VERSION 5.7 ;
  NOWIREEXTENSIONATPIN ON ;
  DIVIDERCHAR "/" ;
  BUSBITCHARS "[]" ;
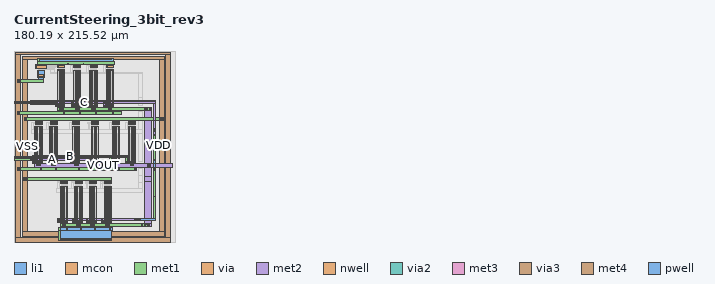
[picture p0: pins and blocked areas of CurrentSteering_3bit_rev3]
MACRO CurrentSteering_3bit_rev3
  CLASS BLOCK ;
  FOREIGN CurrentSteering_3bit_rev3 ;
  ORIGIN -36.730 137.180 ;
  SIZE 180.190 BY 215.520 ;
  PIN A
    ANTENNAGATEAREA 400.000000 ;
    PORT
      LAYER li1 ;
        RECT 103.560 -6.460 104.060 -6.290 ;
        RECT 104.350 -6.460 104.850 -6.290 ;
        RECT 105.140 -6.460 105.640 -6.290 ;
        RECT 105.930 -6.460 106.430 -6.290 ;
        RECT 106.720 -6.460 107.220 -6.290 ;
        RECT 107.510 -6.460 108.010 -6.290 ;
        RECT 108.300 -6.460 108.800 -6.290 ;
        RECT 109.090 -6.460 109.590 -6.290 ;
        RECT 109.880 -6.460 110.380 -6.290 ;
        RECT 110.670 -6.460 111.170 -6.290 ;
        RECT 124.580 -6.460 125.080 -6.290 ;
        RECT 125.370 -6.460 125.870 -6.290 ;
        RECT 126.160 -6.460 126.660 -6.290 ;
        RECT 126.950 -6.460 127.450 -6.290 ;
        RECT 127.740 -6.460 128.240 -6.290 ;
        RECT 128.530 -6.460 129.030 -6.290 ;
        RECT 129.320 -6.460 129.820 -6.290 ;
        RECT 130.110 -6.460 130.610 -6.290 ;
        RECT 130.900 -6.460 131.400 -6.290 ;
        RECT 131.690 -6.460 132.190 -6.290 ;
        RECT 103.560 -47.010 104.060 -46.840 ;
        RECT 104.350 -47.010 104.850 -46.840 ;
        RECT 105.140 -47.010 105.640 -46.840 ;
        RECT 105.930 -47.010 106.430 -46.840 ;
        RECT 106.720 -47.010 107.220 -46.840 ;
        RECT 107.510 -47.010 108.010 -46.840 ;
        RECT 108.300 -47.010 108.800 -46.840 ;
        RECT 109.090 -47.010 109.590 -46.840 ;
        RECT 109.880 -47.010 110.380 -46.840 ;
        RECT 110.670 -47.010 111.170 -46.840 ;
        RECT 124.580 -47.010 125.080 -46.840 ;
        RECT 125.370 -47.010 125.870 -46.840 ;
        RECT 126.160 -47.010 126.660 -46.840 ;
        RECT 126.950 -47.010 127.450 -46.840 ;
        RECT 127.740 -47.010 128.240 -46.840 ;
        RECT 128.530 -47.010 129.030 -46.840 ;
        RECT 129.320 -47.010 129.820 -46.840 ;
        RECT 130.110 -47.010 130.610 -46.840 ;
        RECT 130.900 -47.010 131.400 -46.840 ;
        RECT 131.690 -47.010 132.190 -46.840 ;
      LAYER mcon ;
        RECT 103.640 -6.460 103.980 -6.290 ;
        RECT 104.430 -6.460 104.770 -6.290 ;
        RECT 105.220 -6.460 105.560 -6.290 ;
        RECT 106.010 -6.460 106.350 -6.290 ;
        RECT 106.800 -6.460 107.140 -6.290 ;
        RECT 107.590 -6.460 107.930 -6.290 ;
        RECT 108.380 -6.460 108.720 -6.290 ;
        RECT 109.170 -6.460 109.510 -6.290 ;
        RECT 109.960 -6.460 110.300 -6.290 ;
        RECT 110.750 -6.460 111.090 -6.290 ;
        RECT 124.660 -6.460 125.000 -6.290 ;
        RECT 125.450 -6.460 125.790 -6.290 ;
        RECT 126.240 -6.460 126.580 -6.290 ;
        RECT 127.030 -6.460 127.370 -6.290 ;
        RECT 127.820 -6.460 128.160 -6.290 ;
        RECT 128.610 -6.460 128.950 -6.290 ;
        RECT 129.400 -6.460 129.740 -6.290 ;
        RECT 130.190 -6.460 130.530 -6.290 ;
        RECT 130.980 -6.460 131.320 -6.290 ;
        RECT 131.770 -6.460 132.110 -6.290 ;
        RECT 103.640 -47.010 103.980 -46.840 ;
        RECT 104.430 -47.010 104.770 -46.840 ;
        RECT 105.220 -47.010 105.560 -46.840 ;
        RECT 106.010 -47.010 106.350 -46.840 ;
        RECT 106.800 -47.010 107.140 -46.840 ;
        RECT 107.590 -47.010 107.930 -46.840 ;
        RECT 108.380 -47.010 108.720 -46.840 ;
        RECT 109.170 -47.010 109.510 -46.840 ;
        RECT 109.960 -47.010 110.300 -46.840 ;
        RECT 110.750 -47.010 111.090 -46.840 ;
        RECT 124.660 -47.010 125.000 -46.840 ;
        RECT 125.450 -47.010 125.790 -46.840 ;
        RECT 126.240 -47.010 126.580 -46.840 ;
        RECT 127.030 -47.010 127.370 -46.840 ;
        RECT 127.820 -47.010 128.160 -46.840 ;
        RECT 128.610 -47.010 128.950 -46.840 ;
        RECT 129.400 -47.010 129.740 -46.840 ;
        RECT 130.190 -47.010 130.530 -46.840 ;
        RECT 130.980 -47.010 131.320 -46.840 ;
        RECT 131.770 -47.010 132.110 -46.840 ;
      LAYER met1 ;
        RECT 103.580 -6.490 104.040 -6.260 ;
        RECT 104.370 -6.490 104.830 -6.260 ;
        RECT 105.160 -6.490 105.620 -6.260 ;
        RECT 105.950 -6.490 106.410 -6.260 ;
        RECT 106.740 -6.490 107.200 -6.260 ;
        RECT 107.530 -6.490 107.990 -6.260 ;
        RECT 108.320 -6.490 108.780 -6.260 ;
        RECT 109.110 -6.490 109.570 -6.260 ;
        RECT 109.900 -6.490 110.360 -6.260 ;
        RECT 110.690 -6.490 111.150 -6.260 ;
        RECT 124.600 -6.490 125.060 -6.260 ;
        RECT 125.390 -6.490 125.850 -6.260 ;
        RECT 126.180 -6.490 126.640 -6.260 ;
        RECT 126.970 -6.490 127.430 -6.260 ;
        RECT 127.760 -6.490 128.220 -6.260 ;
        RECT 128.550 -6.490 129.010 -6.260 ;
        RECT 129.340 -6.490 129.800 -6.260 ;
        RECT 130.130 -6.490 130.590 -6.260 ;
        RECT 130.920 -6.490 131.380 -6.260 ;
        RECT 131.710 -6.490 132.170 -6.260 ;
        RECT 36.820 -44.710 56.630 -42.990 ;
        RECT 100.420 -46.630 102.110 -43.730 ;
        RECT 121.430 -46.630 123.170 -43.610 ;
        RECT 100.420 -46.810 102.230 -46.630 ;
        RECT 121.430 -46.810 123.250 -46.630 ;
        RECT 100.420 -47.230 111.190 -46.810 ;
        RECT 121.430 -47.230 132.210 -46.810 ;
        RECT 100.420 -47.500 102.230 -47.230 ;
        RECT 121.430 -47.500 123.250 -47.230 ;
        RECT 100.420 -47.790 102.110 -47.500 ;
        RECT 121.430 -47.800 123.170 -47.500 ;
      LAYER via ;
        RECT 55.340 -44.390 56.190 -43.540 ;
        RECT 100.800 -44.530 101.880 -43.850 ;
        RECT 121.860 -44.510 122.590 -44.040 ;
        RECT 100.650 -47.550 101.730 -46.870 ;
        RECT 121.960 -47.540 122.690 -47.070 ;
      LAYER met2 ;
        RECT 57.260 -42.990 123.170 -42.980 ;
        RECT 36.820 -44.680 123.170 -42.990 ;
        RECT 36.820 -44.710 56.630 -44.680 ;
        RECT 57.260 -44.690 123.170 -44.680 ;
        RECT 100.420 -47.790 102.110 -44.690 ;
        RECT 121.430 -47.800 123.170 -44.690 ;
    END
  END A
  PIN B
    ANTENNAGATEAREA 800.000000 ;
    PORT
      LAYER li1 ;
        RECT 60.670 -6.440 61.170 -6.270 ;
        RECT 61.460 -6.440 61.960 -6.270 ;
        RECT 62.250 -6.440 62.750 -6.270 ;
        RECT 63.040 -6.440 63.540 -6.270 ;
        RECT 63.830 -6.440 64.330 -6.270 ;
        RECT 64.620 -6.440 65.120 -6.270 ;
        RECT 65.410 -6.440 65.910 -6.270 ;
        RECT 66.200 -6.440 66.700 -6.270 ;
        RECT 66.990 -6.440 67.490 -6.270 ;
        RECT 67.780 -6.440 68.280 -6.270 ;
        RECT 77.720 -6.440 78.220 -6.270 ;
        RECT 78.510 -6.440 79.010 -6.270 ;
        RECT 79.300 -6.440 79.800 -6.270 ;
        RECT 80.090 -6.440 80.590 -6.270 ;
        RECT 80.880 -6.440 81.380 -6.270 ;
        RECT 81.670 -6.440 82.170 -6.270 ;
        RECT 82.460 -6.440 82.960 -6.270 ;
        RECT 83.250 -6.440 83.750 -6.270 ;
        RECT 84.040 -6.440 84.540 -6.270 ;
        RECT 84.830 -6.440 85.330 -6.270 ;
        RECT 148.650 -6.490 149.150 -6.320 ;
        RECT 149.440 -6.490 149.940 -6.320 ;
        RECT 150.230 -6.490 150.730 -6.320 ;
        RECT 151.020 -6.490 151.520 -6.320 ;
        RECT 151.810 -6.490 152.310 -6.320 ;
        RECT 152.600 -6.490 153.100 -6.320 ;
        RECT 153.390 -6.490 153.890 -6.320 ;
        RECT 154.180 -6.490 154.680 -6.320 ;
        RECT 154.970 -6.490 155.470 -6.320 ;
        RECT 155.760 -6.490 156.260 -6.320 ;
        RECT 166.720 -6.490 167.220 -6.320 ;
        RECT 167.510 -6.490 168.010 -6.320 ;
        RECT 168.300 -6.490 168.800 -6.320 ;
        RECT 169.090 -6.490 169.590 -6.320 ;
        RECT 169.880 -6.490 170.380 -6.320 ;
        RECT 170.670 -6.490 171.170 -6.320 ;
        RECT 171.460 -6.490 171.960 -6.320 ;
        RECT 172.250 -6.490 172.750 -6.320 ;
        RECT 173.040 -6.490 173.540 -6.320 ;
        RECT 173.830 -6.490 174.330 -6.320 ;
        RECT 60.670 -46.990 61.170 -46.820 ;
        RECT 61.460 -46.990 61.960 -46.820 ;
        RECT 62.250 -46.990 62.750 -46.820 ;
        RECT 63.040 -46.990 63.540 -46.820 ;
        RECT 63.830 -46.990 64.330 -46.820 ;
        RECT 64.620 -46.990 65.120 -46.820 ;
        RECT 65.410 -46.990 65.910 -46.820 ;
        RECT 66.200 -46.990 66.700 -46.820 ;
        RECT 66.990 -46.990 67.490 -46.820 ;
        RECT 67.780 -46.990 68.280 -46.820 ;
        RECT 77.720 -46.990 78.220 -46.820 ;
        RECT 78.510 -46.990 79.010 -46.820 ;
        RECT 79.300 -46.990 79.800 -46.820 ;
        RECT 80.090 -46.990 80.590 -46.820 ;
        RECT 80.880 -46.990 81.380 -46.820 ;
        RECT 81.670 -46.990 82.170 -46.820 ;
        RECT 82.460 -46.990 82.960 -46.820 ;
        RECT 83.250 -46.990 83.750 -46.820 ;
        RECT 84.040 -46.990 84.540 -46.820 ;
        RECT 84.830 -46.990 85.330 -46.820 ;
        RECT 148.650 -47.040 149.150 -46.870 ;
        RECT 149.440 -47.040 149.940 -46.870 ;
        RECT 150.230 -47.040 150.730 -46.870 ;
        RECT 151.020 -47.040 151.520 -46.870 ;
        RECT 151.810 -47.040 152.310 -46.870 ;
        RECT 152.600 -47.040 153.100 -46.870 ;
        RECT 153.390 -47.040 153.890 -46.870 ;
        RECT 154.180 -47.040 154.680 -46.870 ;
        RECT 154.970 -47.040 155.470 -46.870 ;
        RECT 155.760 -47.040 156.260 -46.870 ;
        RECT 166.720 -47.040 167.220 -46.870 ;
        RECT 167.510 -47.040 168.010 -46.870 ;
        RECT 168.300 -47.040 168.800 -46.870 ;
        RECT 169.090 -47.040 169.590 -46.870 ;
        RECT 169.880 -47.040 170.380 -46.870 ;
        RECT 170.670 -47.040 171.170 -46.870 ;
        RECT 171.460 -47.040 171.960 -46.870 ;
        RECT 172.250 -47.040 172.750 -46.870 ;
        RECT 173.040 -47.040 173.540 -46.870 ;
        RECT 173.830 -47.040 174.330 -46.870 ;
      LAYER mcon ;
        RECT 60.750 -6.440 61.090 -6.270 ;
        RECT 61.540 -6.440 61.880 -6.270 ;
        RECT 62.330 -6.440 62.670 -6.270 ;
        RECT 63.120 -6.440 63.460 -6.270 ;
        RECT 63.910 -6.440 64.250 -6.270 ;
        RECT 64.700 -6.440 65.040 -6.270 ;
        RECT 65.490 -6.440 65.830 -6.270 ;
        RECT 66.280 -6.440 66.620 -6.270 ;
        RECT 67.070 -6.440 67.410 -6.270 ;
        RECT 67.860 -6.440 68.200 -6.270 ;
        RECT 77.800 -6.440 78.140 -6.270 ;
        RECT 78.590 -6.440 78.930 -6.270 ;
        RECT 79.380 -6.440 79.720 -6.270 ;
        RECT 80.170 -6.440 80.510 -6.270 ;
        RECT 80.960 -6.440 81.300 -6.270 ;
        RECT 81.750 -6.440 82.090 -6.270 ;
        RECT 82.540 -6.440 82.880 -6.270 ;
        RECT 83.330 -6.440 83.670 -6.270 ;
        RECT 84.120 -6.440 84.460 -6.270 ;
        RECT 84.910 -6.440 85.250 -6.270 ;
        RECT 148.730 -6.490 149.070 -6.320 ;
        RECT 149.520 -6.490 149.860 -6.320 ;
        RECT 150.310 -6.490 150.650 -6.320 ;
        RECT 151.100 -6.490 151.440 -6.320 ;
        RECT 151.890 -6.490 152.230 -6.320 ;
        RECT 152.680 -6.490 153.020 -6.320 ;
        RECT 153.470 -6.490 153.810 -6.320 ;
        RECT 154.260 -6.490 154.600 -6.320 ;
        RECT 155.050 -6.490 155.390 -6.320 ;
        RECT 155.840 -6.490 156.180 -6.320 ;
        RECT 166.800 -6.490 167.140 -6.320 ;
        RECT 167.590 -6.490 167.930 -6.320 ;
        RECT 168.380 -6.490 168.720 -6.320 ;
        RECT 169.170 -6.490 169.510 -6.320 ;
        RECT 169.960 -6.490 170.300 -6.320 ;
        RECT 170.750 -6.490 171.090 -6.320 ;
        RECT 171.540 -6.490 171.880 -6.320 ;
        RECT 172.330 -6.490 172.670 -6.320 ;
        RECT 173.120 -6.490 173.460 -6.320 ;
        RECT 173.910 -6.490 174.250 -6.320 ;
        RECT 60.750 -46.990 61.090 -46.820 ;
        RECT 61.540 -46.990 61.880 -46.820 ;
        RECT 62.330 -46.990 62.670 -46.820 ;
        RECT 63.120 -46.990 63.460 -46.820 ;
        RECT 63.910 -46.990 64.250 -46.820 ;
        RECT 64.700 -46.990 65.040 -46.820 ;
        RECT 65.490 -46.990 65.830 -46.820 ;
        RECT 66.280 -46.990 66.620 -46.820 ;
        RECT 67.070 -46.990 67.410 -46.820 ;
        RECT 67.860 -46.990 68.200 -46.820 ;
        RECT 77.800 -46.990 78.140 -46.820 ;
        RECT 78.590 -46.990 78.930 -46.820 ;
        RECT 79.380 -46.990 79.720 -46.820 ;
        RECT 80.170 -46.990 80.510 -46.820 ;
        RECT 80.960 -46.990 81.300 -46.820 ;
        RECT 81.750 -46.990 82.090 -46.820 ;
        RECT 82.540 -46.990 82.880 -46.820 ;
        RECT 83.330 -46.990 83.670 -46.820 ;
        RECT 84.120 -46.990 84.460 -46.820 ;
        RECT 84.910 -46.990 85.250 -46.820 ;
        RECT 148.730 -47.040 149.070 -46.870 ;
        RECT 149.520 -47.040 149.860 -46.870 ;
        RECT 150.310 -47.040 150.650 -46.870 ;
        RECT 151.100 -47.040 151.440 -46.870 ;
        RECT 151.890 -47.040 152.230 -46.870 ;
        RECT 152.680 -47.040 153.020 -46.870 ;
        RECT 153.470 -47.040 153.810 -46.870 ;
        RECT 154.260 -47.040 154.600 -46.870 ;
        RECT 155.050 -47.040 155.390 -46.870 ;
        RECT 155.840 -47.040 156.180 -46.870 ;
        RECT 166.800 -47.040 167.140 -46.870 ;
        RECT 167.590 -47.040 167.930 -46.870 ;
        RECT 168.380 -47.040 168.720 -46.870 ;
        RECT 169.170 -47.040 169.510 -46.870 ;
        RECT 169.960 -47.040 170.300 -46.870 ;
        RECT 170.750 -47.040 171.090 -46.870 ;
        RECT 171.540 -47.040 171.880 -46.870 ;
        RECT 172.330 -47.040 172.670 -46.870 ;
        RECT 173.120 -47.040 173.460 -46.870 ;
        RECT 173.910 -47.040 174.250 -46.870 ;
      LAYER met1 ;
        RECT 60.690 -6.470 61.150 -6.240 ;
        RECT 61.480 -6.470 61.940 -6.240 ;
        RECT 62.270 -6.470 62.730 -6.240 ;
        RECT 63.060 -6.470 63.520 -6.240 ;
        RECT 63.850 -6.470 64.310 -6.240 ;
        RECT 64.640 -6.470 65.100 -6.240 ;
        RECT 65.430 -6.470 65.890 -6.240 ;
        RECT 66.220 -6.470 66.680 -6.240 ;
        RECT 67.010 -6.470 67.470 -6.240 ;
        RECT 67.800 -6.470 68.260 -6.240 ;
        RECT 77.740 -6.470 78.200 -6.240 ;
        RECT 78.530 -6.470 78.990 -6.240 ;
        RECT 79.320 -6.470 79.780 -6.240 ;
        RECT 80.110 -6.470 80.570 -6.240 ;
        RECT 80.900 -6.470 81.360 -6.240 ;
        RECT 81.690 -6.470 82.150 -6.240 ;
        RECT 82.480 -6.470 82.940 -6.240 ;
        RECT 83.270 -6.470 83.730 -6.240 ;
        RECT 84.060 -6.470 84.520 -6.240 ;
        RECT 84.850 -6.470 85.310 -6.240 ;
        RECT 148.670 -6.520 149.130 -6.290 ;
        RECT 149.460 -6.520 149.920 -6.290 ;
        RECT 150.250 -6.520 150.710 -6.290 ;
        RECT 151.040 -6.520 151.500 -6.290 ;
        RECT 151.830 -6.520 152.290 -6.290 ;
        RECT 152.620 -6.520 153.080 -6.290 ;
        RECT 153.410 -6.520 153.870 -6.290 ;
        RECT 154.200 -6.520 154.660 -6.290 ;
        RECT 154.990 -6.520 155.450 -6.290 ;
        RECT 155.780 -6.520 156.240 -6.290 ;
        RECT 166.740 -6.520 167.200 -6.290 ;
        RECT 167.530 -6.520 167.990 -6.290 ;
        RECT 168.320 -6.520 168.780 -6.290 ;
        RECT 169.110 -6.520 169.570 -6.290 ;
        RECT 169.900 -6.520 170.360 -6.290 ;
        RECT 170.690 -6.520 171.150 -6.290 ;
        RECT 171.480 -6.520 171.940 -6.290 ;
        RECT 172.270 -6.520 172.730 -6.290 ;
        RECT 173.060 -6.520 173.520 -6.290 ;
        RECT 173.850 -6.520 174.310 -6.290 ;
        RECT 55.650 -39.750 58.240 -39.740 ;
        RECT 36.820 -40.080 58.240 -39.750 ;
        RECT 36.820 -41.430 59.140 -40.080 ;
        RECT 36.820 -41.540 57.000 -41.430 ;
        RECT 57.500 -46.250 59.140 -41.430 ;
        RECT 57.500 -46.610 59.150 -46.250 ;
        RECT 74.560 -46.610 76.200 -40.040 ;
        RECT 57.500 -46.790 59.340 -46.610 ;
        RECT 74.560 -46.790 76.390 -46.610 ;
        RECT 145.490 -46.660 147.220 -40.560 ;
        RECT 163.560 -46.300 165.050 -40.630 ;
        RECT 163.560 -46.660 165.200 -46.300 ;
        RECT 57.500 -47.210 68.300 -46.790 ;
        RECT 74.560 -47.210 85.350 -46.790 ;
        RECT 145.490 -46.840 147.320 -46.660 ;
        RECT 163.560 -46.840 165.390 -46.660 ;
        RECT 57.500 -47.480 59.340 -47.210 ;
        RECT 74.560 -47.480 76.390 -47.210 ;
        RECT 145.490 -47.260 156.280 -46.840 ;
        RECT 163.560 -47.260 174.350 -46.840 ;
        RECT 57.500 -47.770 59.150 -47.480 ;
        RECT 74.560 -47.770 76.200 -47.480 ;
        RECT 145.490 -47.530 147.320 -47.260 ;
        RECT 163.560 -47.530 165.390 -47.260 ;
        RECT 57.500 -47.810 59.140 -47.770 ;
        RECT 145.490 -47.850 147.220 -47.530 ;
        RECT 163.560 -47.820 165.200 -47.530 ;
        RECT 163.560 -47.870 165.050 -47.820 ;
      LAYER via ;
        RECT 55.250 -41.080 56.100 -40.230 ;
        RECT 57.780 -41.310 58.890 -40.150 ;
        RECT 74.810 -41.360 75.920 -40.200 ;
        RECT 145.890 -41.370 146.640 -40.830 ;
        RECT 163.750 -41.410 164.700 -40.900 ;
        RECT 146.020 -47.540 146.770 -47.000 ;
        RECT 163.830 -47.510 164.780 -47.000 ;
      LAYER met2 ;
        RECT 36.820 -39.780 57.000 -39.750 ;
        RECT 57.300 -39.780 165.060 -39.620 ;
        RECT 36.820 -41.470 165.060 -39.780 ;
        RECT 36.820 -41.540 57.000 -41.470 ;
        RECT 57.300 -41.540 165.060 -41.470 ;
        RECT 145.490 -47.850 147.220 -41.540 ;
        RECT 163.560 -47.870 165.050 -41.540 ;
    END
  END B
  PIN C
    ANTENNAGATEAREA 1600.000000 ;
    PORT
      LAYER li1 ;
        RECT 86.480 57.790 86.980 57.960 ;
        RECT 87.270 57.790 87.770 57.960 ;
        RECT 88.060 57.790 88.560 57.960 ;
        RECT 88.850 57.790 89.350 57.960 ;
        RECT 89.640 57.790 90.140 57.960 ;
        RECT 90.430 57.790 90.930 57.960 ;
        RECT 91.220 57.790 91.720 57.960 ;
        RECT 92.010 57.790 92.510 57.960 ;
        RECT 92.800 57.790 93.300 57.960 ;
        RECT 93.590 57.790 94.090 57.960 ;
        RECT 104.710 57.630 105.210 57.800 ;
        RECT 105.500 57.630 106.000 57.800 ;
        RECT 106.290 57.630 106.790 57.800 ;
        RECT 107.080 57.630 107.580 57.800 ;
        RECT 107.870 57.630 108.370 57.800 ;
        RECT 108.660 57.630 109.160 57.800 ;
        RECT 109.450 57.630 109.950 57.800 ;
        RECT 110.240 57.630 110.740 57.800 ;
        RECT 111.030 57.630 111.530 57.800 ;
        RECT 111.820 57.630 112.320 57.800 ;
        RECT 123.110 57.580 123.610 57.750 ;
        RECT 123.900 57.580 124.400 57.750 ;
        RECT 124.690 57.580 125.190 57.750 ;
        RECT 125.480 57.580 125.980 57.750 ;
        RECT 126.270 57.580 126.770 57.750 ;
        RECT 127.060 57.580 127.560 57.750 ;
        RECT 127.850 57.580 128.350 57.750 ;
        RECT 128.640 57.580 129.140 57.750 ;
        RECT 129.430 57.580 129.930 57.750 ;
        RECT 130.220 57.580 130.720 57.750 ;
        RECT 141.880 57.730 142.380 57.900 ;
        RECT 142.670 57.730 143.170 57.900 ;
        RECT 143.460 57.730 143.960 57.900 ;
        RECT 144.250 57.730 144.750 57.900 ;
        RECT 145.040 57.730 145.540 57.900 ;
        RECT 145.830 57.730 146.330 57.900 ;
        RECT 146.620 57.730 147.120 57.900 ;
        RECT 147.410 57.730 147.910 57.900 ;
        RECT 148.200 57.730 148.700 57.900 ;
        RECT 148.990 57.730 149.490 57.900 ;
        RECT 86.480 17.240 86.980 17.410 ;
        RECT 87.270 17.240 87.770 17.410 ;
        RECT 88.060 17.240 88.560 17.410 ;
        RECT 88.850 17.240 89.350 17.410 ;
        RECT 89.640 17.240 90.140 17.410 ;
        RECT 90.430 17.240 90.930 17.410 ;
        RECT 91.220 17.240 91.720 17.410 ;
        RECT 92.010 17.240 92.510 17.410 ;
        RECT 92.800 17.240 93.300 17.410 ;
        RECT 93.590 17.240 94.090 17.410 ;
        RECT 104.710 17.080 105.210 17.250 ;
        RECT 105.500 17.080 106.000 17.250 ;
        RECT 106.290 17.080 106.790 17.250 ;
        RECT 107.080 17.080 107.580 17.250 ;
        RECT 107.870 17.080 108.370 17.250 ;
        RECT 108.660 17.080 109.160 17.250 ;
        RECT 109.450 17.080 109.950 17.250 ;
        RECT 110.240 17.080 110.740 17.250 ;
        RECT 111.030 17.080 111.530 17.250 ;
        RECT 111.820 17.080 112.320 17.250 ;
        RECT 123.110 17.030 123.610 17.200 ;
        RECT 123.900 17.030 124.400 17.200 ;
        RECT 124.690 17.030 125.190 17.200 ;
        RECT 125.480 17.030 125.980 17.200 ;
        RECT 126.270 17.030 126.770 17.200 ;
        RECT 127.060 17.030 127.560 17.200 ;
        RECT 127.850 17.030 128.350 17.200 ;
        RECT 128.640 17.030 129.140 17.200 ;
        RECT 129.430 17.030 129.930 17.200 ;
        RECT 130.220 17.030 130.720 17.200 ;
        RECT 141.880 17.180 142.380 17.350 ;
        RECT 142.670 17.180 143.170 17.350 ;
        RECT 143.460 17.180 143.960 17.350 ;
        RECT 144.250 17.180 144.750 17.350 ;
        RECT 145.040 17.180 145.540 17.350 ;
        RECT 145.830 17.180 146.330 17.350 ;
        RECT 146.620 17.180 147.120 17.350 ;
        RECT 147.410 17.180 147.910 17.350 ;
        RECT 148.200 17.180 148.700 17.350 ;
        RECT 148.990 17.180 149.490 17.350 ;
        RECT 89.760 -74.150 90.260 -73.980 ;
        RECT 90.550 -74.150 91.050 -73.980 ;
        RECT 91.340 -74.150 91.840 -73.980 ;
        RECT 92.130 -74.150 92.630 -73.980 ;
        RECT 92.920 -74.150 93.420 -73.980 ;
        RECT 93.710 -74.150 94.210 -73.980 ;
        RECT 94.500 -74.150 95.000 -73.980 ;
        RECT 95.290 -74.150 95.790 -73.980 ;
        RECT 96.080 -74.150 96.580 -73.980 ;
        RECT 96.870 -74.150 97.370 -73.980 ;
        RECT 106.150 -74.150 106.650 -73.980 ;
        RECT 106.940 -74.150 107.440 -73.980 ;
        RECT 107.730 -74.150 108.230 -73.980 ;
        RECT 108.520 -74.150 109.020 -73.980 ;
        RECT 109.310 -74.150 109.810 -73.980 ;
        RECT 110.100 -74.150 110.600 -73.980 ;
        RECT 110.890 -74.150 111.390 -73.980 ;
        RECT 111.680 -74.150 112.180 -73.980 ;
        RECT 112.470 -74.150 112.970 -73.980 ;
        RECT 113.260 -74.150 113.760 -73.980 ;
        RECT 122.110 -74.150 122.610 -73.980 ;
        RECT 122.900 -74.150 123.400 -73.980 ;
        RECT 123.690 -74.150 124.190 -73.980 ;
        RECT 124.480 -74.150 124.980 -73.980 ;
        RECT 125.270 -74.150 125.770 -73.980 ;
        RECT 126.060 -74.150 126.560 -73.980 ;
        RECT 126.850 -74.150 127.350 -73.980 ;
        RECT 127.640 -74.150 128.140 -73.980 ;
        RECT 128.430 -74.150 128.930 -73.980 ;
        RECT 129.220 -74.150 129.720 -73.980 ;
        RECT 139.100 -74.150 139.600 -73.980 ;
        RECT 139.890 -74.150 140.390 -73.980 ;
        RECT 140.680 -74.150 141.180 -73.980 ;
        RECT 141.470 -74.150 141.970 -73.980 ;
        RECT 142.260 -74.150 142.760 -73.980 ;
        RECT 143.050 -74.150 143.550 -73.980 ;
        RECT 143.840 -74.150 144.340 -73.980 ;
        RECT 144.630 -74.150 145.130 -73.980 ;
        RECT 145.420 -74.150 145.920 -73.980 ;
        RECT 146.210 -74.150 146.710 -73.980 ;
        RECT 194.450 -110.000 197.690 -8.410 ;
        RECT 173.110 -112.650 197.690 -110.000 ;
        RECT 173.110 -112.710 197.640 -112.650 ;
        RECT 194.450 -112.750 197.640 -112.710 ;
        RECT 89.760 -114.700 90.260 -114.530 ;
        RECT 90.550 -114.700 91.050 -114.530 ;
        RECT 91.340 -114.700 91.840 -114.530 ;
        RECT 92.130 -114.700 92.630 -114.530 ;
        RECT 92.920 -114.700 93.420 -114.530 ;
        RECT 93.710 -114.700 94.210 -114.530 ;
        RECT 94.500 -114.700 95.000 -114.530 ;
        RECT 95.290 -114.700 95.790 -114.530 ;
        RECT 96.080 -114.700 96.580 -114.530 ;
        RECT 96.870 -114.700 97.370 -114.530 ;
        RECT 106.150 -114.700 106.650 -114.530 ;
        RECT 106.940 -114.700 107.440 -114.530 ;
        RECT 107.730 -114.700 108.230 -114.530 ;
        RECT 108.520 -114.700 109.020 -114.530 ;
        RECT 109.310 -114.700 109.810 -114.530 ;
        RECT 110.100 -114.700 110.600 -114.530 ;
        RECT 110.890 -114.700 111.390 -114.530 ;
        RECT 111.680 -114.700 112.180 -114.530 ;
        RECT 112.470 -114.700 112.970 -114.530 ;
        RECT 113.260 -114.700 113.760 -114.530 ;
        RECT 122.110 -114.700 122.610 -114.530 ;
        RECT 122.900 -114.700 123.400 -114.530 ;
        RECT 123.690 -114.700 124.190 -114.530 ;
        RECT 124.480 -114.700 124.980 -114.530 ;
        RECT 125.270 -114.700 125.770 -114.530 ;
        RECT 126.060 -114.700 126.560 -114.530 ;
        RECT 126.850 -114.700 127.350 -114.530 ;
        RECT 127.640 -114.700 128.140 -114.530 ;
        RECT 128.430 -114.700 128.930 -114.530 ;
        RECT 129.220 -114.700 129.720 -114.530 ;
        RECT 139.100 -114.700 139.600 -114.530 ;
        RECT 139.890 -114.700 140.390 -114.530 ;
        RECT 140.680 -114.700 141.180 -114.530 ;
        RECT 141.470 -114.700 141.970 -114.530 ;
        RECT 142.260 -114.700 142.760 -114.530 ;
        RECT 143.050 -114.700 143.550 -114.530 ;
        RECT 143.840 -114.700 144.340 -114.530 ;
        RECT 144.630 -114.700 145.130 -114.530 ;
        RECT 145.420 -114.700 145.920 -114.530 ;
        RECT 146.210 -114.700 146.710 -114.530 ;
      LAYER mcon ;
        RECT 86.560 57.790 86.900 57.960 ;
        RECT 87.350 57.790 87.690 57.960 ;
        RECT 88.140 57.790 88.480 57.960 ;
        RECT 88.930 57.790 89.270 57.960 ;
        RECT 89.720 57.790 90.060 57.960 ;
        RECT 90.510 57.790 90.850 57.960 ;
        RECT 91.300 57.790 91.640 57.960 ;
        RECT 92.090 57.790 92.430 57.960 ;
        RECT 92.880 57.790 93.220 57.960 ;
        RECT 93.670 57.790 94.010 57.960 ;
        RECT 104.790 57.630 105.130 57.800 ;
        RECT 105.580 57.630 105.920 57.800 ;
        RECT 106.370 57.630 106.710 57.800 ;
        RECT 107.160 57.630 107.500 57.800 ;
        RECT 107.950 57.630 108.290 57.800 ;
        RECT 108.740 57.630 109.080 57.800 ;
        RECT 109.530 57.630 109.870 57.800 ;
        RECT 110.320 57.630 110.660 57.800 ;
        RECT 111.110 57.630 111.450 57.800 ;
        RECT 111.900 57.630 112.240 57.800 ;
        RECT 123.190 57.580 123.530 57.750 ;
        RECT 123.980 57.580 124.320 57.750 ;
        RECT 124.770 57.580 125.110 57.750 ;
        RECT 125.560 57.580 125.900 57.750 ;
        RECT 126.350 57.580 126.690 57.750 ;
        RECT 127.140 57.580 127.480 57.750 ;
        RECT 127.930 57.580 128.270 57.750 ;
        RECT 128.720 57.580 129.060 57.750 ;
        RECT 129.510 57.580 129.850 57.750 ;
        RECT 130.300 57.580 130.640 57.750 ;
        RECT 141.960 57.730 142.300 57.900 ;
        RECT 142.750 57.730 143.090 57.900 ;
        RECT 143.540 57.730 143.880 57.900 ;
        RECT 144.330 57.730 144.670 57.900 ;
        RECT 145.120 57.730 145.460 57.900 ;
        RECT 145.910 57.730 146.250 57.900 ;
        RECT 146.700 57.730 147.040 57.900 ;
        RECT 147.490 57.730 147.830 57.900 ;
        RECT 148.280 57.730 148.620 57.900 ;
        RECT 149.070 57.730 149.410 57.900 ;
        RECT 86.560 17.240 86.900 17.410 ;
        RECT 87.350 17.240 87.690 17.410 ;
        RECT 88.140 17.240 88.480 17.410 ;
        RECT 88.930 17.240 89.270 17.410 ;
        RECT 89.720 17.240 90.060 17.410 ;
        RECT 90.510 17.240 90.850 17.410 ;
        RECT 91.300 17.240 91.640 17.410 ;
        RECT 92.090 17.240 92.430 17.410 ;
        RECT 92.880 17.240 93.220 17.410 ;
        RECT 93.670 17.240 94.010 17.410 ;
        RECT 104.790 17.080 105.130 17.250 ;
        RECT 105.580 17.080 105.920 17.250 ;
        RECT 106.370 17.080 106.710 17.250 ;
        RECT 107.160 17.080 107.500 17.250 ;
        RECT 107.950 17.080 108.290 17.250 ;
        RECT 108.740 17.080 109.080 17.250 ;
        RECT 109.530 17.080 109.870 17.250 ;
        RECT 110.320 17.080 110.660 17.250 ;
        RECT 111.110 17.080 111.450 17.250 ;
        RECT 111.900 17.080 112.240 17.250 ;
        RECT 123.190 17.030 123.530 17.200 ;
        RECT 123.980 17.030 124.320 17.200 ;
        RECT 124.770 17.030 125.110 17.200 ;
        RECT 125.560 17.030 125.900 17.200 ;
        RECT 126.350 17.030 126.690 17.200 ;
        RECT 127.140 17.030 127.480 17.200 ;
        RECT 127.930 17.030 128.270 17.200 ;
        RECT 128.720 17.030 129.060 17.200 ;
        RECT 129.510 17.030 129.850 17.200 ;
        RECT 130.300 17.030 130.640 17.200 ;
        RECT 141.960 17.180 142.300 17.350 ;
        RECT 142.750 17.180 143.090 17.350 ;
        RECT 143.540 17.180 143.880 17.350 ;
        RECT 144.330 17.180 144.670 17.350 ;
        RECT 145.120 17.180 145.460 17.350 ;
        RECT 145.910 17.180 146.250 17.350 ;
        RECT 146.700 17.180 147.040 17.350 ;
        RECT 147.490 17.180 147.830 17.350 ;
        RECT 148.280 17.180 148.620 17.350 ;
        RECT 149.070 17.180 149.410 17.350 ;
        RECT 194.860 -10.520 195.580 -10.030 ;
        RECT 196.450 -10.570 197.170 -10.080 ;
        RECT 194.830 -11.610 195.550 -11.120 ;
        RECT 196.490 -11.620 197.210 -11.130 ;
        RECT 194.780 -15.480 195.500 -14.990 ;
        RECT 196.470 -15.510 197.190 -15.020 ;
        RECT 194.850 -16.810 195.570 -16.320 ;
        RECT 196.480 -16.850 197.200 -16.360 ;
        RECT 194.770 -43.680 195.490 -43.190 ;
        RECT 196.460 -43.620 197.180 -43.130 ;
        RECT 194.740 -44.520 195.460 -44.030 ;
        RECT 196.420 -44.520 197.140 -44.030 ;
        RECT 194.650 -54.660 195.370 -54.170 ;
        RECT 196.310 -54.650 197.030 -54.160 ;
        RECT 194.680 -55.840 195.400 -55.350 ;
        RECT 196.340 -55.810 197.060 -55.320 ;
        RECT 89.840 -74.150 90.180 -73.980 ;
        RECT 90.630 -74.150 90.970 -73.980 ;
        RECT 91.420 -74.150 91.760 -73.980 ;
        RECT 92.210 -74.150 92.550 -73.980 ;
        RECT 93.000 -74.150 93.340 -73.980 ;
        RECT 93.790 -74.150 94.130 -73.980 ;
        RECT 94.580 -74.150 94.920 -73.980 ;
        RECT 95.370 -74.150 95.710 -73.980 ;
        RECT 96.160 -74.150 96.500 -73.980 ;
        RECT 96.950 -74.150 97.290 -73.980 ;
        RECT 106.230 -74.150 106.570 -73.980 ;
        RECT 107.020 -74.150 107.360 -73.980 ;
        RECT 107.810 -74.150 108.150 -73.980 ;
        RECT 108.600 -74.150 108.940 -73.980 ;
        RECT 109.390 -74.150 109.730 -73.980 ;
        RECT 110.180 -74.150 110.520 -73.980 ;
        RECT 110.970 -74.150 111.310 -73.980 ;
        RECT 111.760 -74.150 112.100 -73.980 ;
        RECT 112.550 -74.150 112.890 -73.980 ;
        RECT 113.340 -74.150 113.680 -73.980 ;
        RECT 122.190 -74.150 122.530 -73.980 ;
        RECT 122.980 -74.150 123.320 -73.980 ;
        RECT 123.770 -74.150 124.110 -73.980 ;
        RECT 124.560 -74.150 124.900 -73.980 ;
        RECT 125.350 -74.150 125.690 -73.980 ;
        RECT 126.140 -74.150 126.480 -73.980 ;
        RECT 126.930 -74.150 127.270 -73.980 ;
        RECT 127.720 -74.150 128.060 -73.980 ;
        RECT 128.510 -74.150 128.850 -73.980 ;
        RECT 129.300 -74.150 129.640 -73.980 ;
        RECT 139.180 -74.150 139.520 -73.980 ;
        RECT 139.970 -74.150 140.310 -73.980 ;
        RECT 140.760 -74.150 141.100 -73.980 ;
        RECT 141.550 -74.150 141.890 -73.980 ;
        RECT 142.340 -74.150 142.680 -73.980 ;
        RECT 143.130 -74.150 143.470 -73.980 ;
        RECT 143.920 -74.150 144.260 -73.980 ;
        RECT 144.710 -74.150 145.050 -73.980 ;
        RECT 145.500 -74.150 145.840 -73.980 ;
        RECT 146.290 -74.150 146.630 -73.980 ;
        RECT 174.630 -110.960 175.410 -110.450 ;
        RECT 176.120 -111.010 176.840 -110.520 ;
        RECT 177.960 -111.070 178.680 -110.580 ;
        RECT 179.820 -111.090 180.540 -110.600 ;
        RECT 174.660 -112.460 175.440 -111.950 ;
        RECT 176.150 -112.440 176.930 -111.930 ;
        RECT 177.940 -112.430 178.660 -111.940 ;
        RECT 179.840 -112.490 180.560 -112.000 ;
        RECT 89.840 -114.700 90.180 -114.530 ;
        RECT 90.630 -114.700 90.970 -114.530 ;
        RECT 91.420 -114.700 91.760 -114.530 ;
        RECT 92.210 -114.700 92.550 -114.530 ;
        RECT 93.000 -114.700 93.340 -114.530 ;
        RECT 93.790 -114.700 94.130 -114.530 ;
        RECT 94.580 -114.700 94.920 -114.530 ;
        RECT 95.370 -114.700 95.710 -114.530 ;
        RECT 96.160 -114.700 96.500 -114.530 ;
        RECT 96.950 -114.700 97.290 -114.530 ;
        RECT 106.230 -114.700 106.570 -114.530 ;
        RECT 107.020 -114.700 107.360 -114.530 ;
        RECT 107.810 -114.700 108.150 -114.530 ;
        RECT 108.600 -114.700 108.940 -114.530 ;
        RECT 109.390 -114.700 109.730 -114.530 ;
        RECT 110.180 -114.700 110.520 -114.530 ;
        RECT 110.970 -114.700 111.310 -114.530 ;
        RECT 111.760 -114.700 112.100 -114.530 ;
        RECT 112.550 -114.700 112.890 -114.530 ;
        RECT 113.340 -114.700 113.680 -114.530 ;
        RECT 122.190 -114.700 122.530 -114.530 ;
        RECT 122.980 -114.700 123.320 -114.530 ;
        RECT 123.770 -114.700 124.110 -114.530 ;
        RECT 124.560 -114.700 124.900 -114.530 ;
        RECT 125.350 -114.700 125.690 -114.530 ;
        RECT 126.140 -114.700 126.480 -114.530 ;
        RECT 126.930 -114.700 127.270 -114.530 ;
        RECT 127.720 -114.700 128.060 -114.530 ;
        RECT 128.510 -114.700 128.850 -114.530 ;
        RECT 129.300 -114.700 129.640 -114.530 ;
        RECT 139.180 -114.700 139.520 -114.530 ;
        RECT 139.970 -114.700 140.310 -114.530 ;
        RECT 140.760 -114.700 141.100 -114.530 ;
        RECT 141.550 -114.700 141.890 -114.530 ;
        RECT 142.340 -114.700 142.680 -114.530 ;
        RECT 143.130 -114.700 143.470 -114.530 ;
        RECT 143.920 -114.700 144.260 -114.530 ;
        RECT 144.710 -114.700 145.050 -114.530 ;
        RECT 145.500 -114.700 145.840 -114.530 ;
        RECT 146.290 -114.700 146.630 -114.530 ;
      LAYER met1 ;
        RECT 86.500 57.760 86.960 57.990 ;
        RECT 87.290 57.760 87.750 57.990 ;
        RECT 88.080 57.760 88.540 57.990 ;
        RECT 88.870 57.760 89.330 57.990 ;
        RECT 89.660 57.760 90.120 57.990 ;
        RECT 90.450 57.760 90.910 57.990 ;
        RECT 91.240 57.760 91.700 57.990 ;
        RECT 92.030 57.760 92.490 57.990 ;
        RECT 92.820 57.760 93.280 57.990 ;
        RECT 93.610 57.760 94.070 57.990 ;
        RECT 104.730 57.600 105.190 57.830 ;
        RECT 105.520 57.600 105.980 57.830 ;
        RECT 106.310 57.600 106.770 57.830 ;
        RECT 107.100 57.600 107.560 57.830 ;
        RECT 107.890 57.600 108.350 57.830 ;
        RECT 108.680 57.600 109.140 57.830 ;
        RECT 109.470 57.600 109.930 57.830 ;
        RECT 110.260 57.600 110.720 57.830 ;
        RECT 111.050 57.600 111.510 57.830 ;
        RECT 111.840 57.600 112.300 57.830 ;
        RECT 123.130 57.550 123.590 57.780 ;
        RECT 123.920 57.550 124.380 57.780 ;
        RECT 124.710 57.550 125.170 57.780 ;
        RECT 125.500 57.550 125.960 57.780 ;
        RECT 126.290 57.550 126.750 57.780 ;
        RECT 127.080 57.550 127.540 57.780 ;
        RECT 127.870 57.550 128.330 57.780 ;
        RECT 128.660 57.550 129.120 57.780 ;
        RECT 129.450 57.550 129.910 57.780 ;
        RECT 130.240 57.550 130.700 57.780 ;
        RECT 141.900 57.700 142.360 57.930 ;
        RECT 142.690 57.700 143.150 57.930 ;
        RECT 143.480 57.700 143.940 57.930 ;
        RECT 144.270 57.700 144.730 57.930 ;
        RECT 145.060 57.700 145.520 57.930 ;
        RECT 145.850 57.700 146.310 57.930 ;
        RECT 146.640 57.700 147.100 57.930 ;
        RECT 147.430 57.700 147.890 57.930 ;
        RECT 148.220 57.700 148.680 57.930 ;
        RECT 149.010 57.700 149.470 57.930 ;
        RECT 55.650 22.090 84.860 22.840 ;
        RECT 36.730 21.210 84.860 22.090 ;
        RECT 36.730 19.660 84.990 21.210 ;
        RECT 55.650 19.070 84.990 19.660 ;
        RECT 83.330 17.620 84.990 19.070 ;
        RECT 83.330 17.440 85.150 17.620 ;
        RECT 101.570 17.460 103.230 21.050 ;
        RECT 83.330 17.020 94.110 17.440 ;
        RECT 101.570 17.280 103.380 17.460 ;
        RECT 119.970 17.410 121.630 20.990 ;
        RECT 138.730 17.560 140.390 21.120 ;
        RECT 83.330 16.750 85.150 17.020 ;
        RECT 101.570 16.860 112.340 17.280 ;
        RECT 119.970 17.230 121.780 17.410 ;
        RECT 138.730 17.380 140.550 17.560 ;
        RECT 83.330 16.460 84.990 16.750 ;
        RECT 101.570 16.590 103.380 16.860 ;
        RECT 119.970 16.810 130.740 17.230 ;
        RECT 138.730 16.960 149.510 17.380 ;
        RECT 101.570 16.300 103.230 16.590 ;
        RECT 119.970 16.540 121.780 16.810 ;
        RECT 138.730 16.690 140.550 16.960 ;
        RECT 119.970 16.240 121.630 16.540 ;
        RECT 138.730 16.370 140.390 16.690 ;
        RECT 194.450 -44.750 197.670 -8.300 ;
        RECT 89.780 -74.180 90.240 -73.950 ;
        RECT 90.570 -74.180 91.030 -73.950 ;
        RECT 91.360 -74.180 91.820 -73.950 ;
        RECT 92.150 -74.180 92.610 -73.950 ;
        RECT 92.940 -74.180 93.400 -73.950 ;
        RECT 93.730 -74.180 94.190 -73.950 ;
        RECT 94.520 -74.180 94.980 -73.950 ;
        RECT 95.310 -74.180 95.770 -73.950 ;
        RECT 96.100 -74.180 96.560 -73.950 ;
        RECT 96.890 -74.180 97.350 -73.950 ;
        RECT 106.170 -74.180 106.630 -73.950 ;
        RECT 106.960 -74.180 107.420 -73.950 ;
        RECT 107.750 -74.180 108.210 -73.950 ;
        RECT 108.540 -74.180 109.000 -73.950 ;
        RECT 109.330 -74.180 109.790 -73.950 ;
        RECT 110.120 -74.180 110.580 -73.950 ;
        RECT 110.910 -74.180 111.370 -73.950 ;
        RECT 111.700 -74.180 112.160 -73.950 ;
        RECT 112.490 -74.180 112.950 -73.950 ;
        RECT 113.280 -74.180 113.740 -73.950 ;
        RECT 122.130 -74.180 122.590 -73.950 ;
        RECT 122.920 -74.180 123.380 -73.950 ;
        RECT 123.710 -74.180 124.170 -73.950 ;
        RECT 124.500 -74.180 124.960 -73.950 ;
        RECT 125.290 -74.180 125.750 -73.950 ;
        RECT 126.080 -74.180 126.540 -73.950 ;
        RECT 126.870 -74.180 127.330 -73.950 ;
        RECT 127.660 -74.180 128.120 -73.950 ;
        RECT 128.450 -74.180 128.910 -73.950 ;
        RECT 129.240 -74.180 129.700 -73.950 ;
        RECT 139.120 -74.180 139.580 -73.950 ;
        RECT 139.910 -74.180 140.370 -73.950 ;
        RECT 140.700 -74.180 141.160 -73.950 ;
        RECT 141.490 -74.180 141.950 -73.950 ;
        RECT 142.280 -74.180 142.740 -73.950 ;
        RECT 143.070 -74.180 143.530 -73.950 ;
        RECT 143.860 -74.180 144.320 -73.950 ;
        RECT 144.650 -74.180 145.110 -73.950 ;
        RECT 145.440 -74.180 145.900 -73.950 ;
        RECT 146.230 -74.180 146.690 -73.950 ;
        RECT 194.450 -86.090 197.640 -53.700 ;
        RECT 194.450 -110.000 197.720 -86.090 ;
        RECT 86.520 -114.320 88.330 -110.690 ;
        RECT 103.000 -114.320 104.700 -111.150 ;
        RECT 118.950 -114.320 120.640 -111.440 ;
        RECT 135.930 -114.320 137.610 -112.190 ;
        RECT 173.110 -112.710 197.720 -110.000 ;
        RECT 194.450 -112.750 197.720 -112.710 ;
        RECT 86.520 -114.500 88.430 -114.320 ;
        RECT 103.000 -114.500 104.820 -114.320 ;
        RECT 118.950 -114.500 120.780 -114.320 ;
        RECT 135.930 -114.500 137.770 -114.320 ;
        RECT 86.520 -114.920 97.390 -114.500 ;
        RECT 103.000 -114.920 113.780 -114.500 ;
        RECT 118.950 -114.920 129.740 -114.500 ;
        RECT 135.930 -114.920 146.730 -114.500 ;
        RECT 86.520 -115.190 88.430 -114.920 ;
        RECT 103.000 -115.190 104.820 -114.920 ;
        RECT 118.950 -115.190 120.780 -114.920 ;
        RECT 135.930 -115.190 137.770 -114.920 ;
        RECT 86.520 -115.490 88.330 -115.190 ;
        RECT 103.000 -115.540 104.700 -115.190 ;
        RECT 118.950 -115.500 120.640 -115.190 ;
        RECT 135.930 -115.480 137.610 -115.190 ;
      LAYER via ;
        RECT 83.840 20.360 84.480 20.840 ;
        RECT 102.030 20.090 102.670 20.570 ;
        RECT 120.490 20.070 121.130 20.550 ;
        RECT 83.840 16.810 84.480 17.290 ;
        RECT 139.160 20.160 139.800 20.640 ;
        RECT 101.990 16.710 102.630 17.190 ;
        RECT 120.370 16.650 121.010 17.130 ;
        RECT 139.230 16.850 139.870 17.330 ;
        RECT 194.860 -9.330 195.580 -8.840 ;
        RECT 196.430 -9.300 197.150 -8.810 ;
        RECT 194.860 -10.520 195.580 -10.030 ;
        RECT 196.450 -10.570 197.170 -10.080 ;
        RECT 194.830 -11.610 195.550 -11.120 ;
        RECT 196.490 -11.620 197.210 -11.130 ;
        RECT 194.780 -15.480 195.500 -14.990 ;
        RECT 196.470 -15.510 197.190 -15.020 ;
        RECT 86.800 -112.240 87.980 -111.050 ;
        RECT 173.260 -110.980 174.040 -110.470 ;
        RECT 174.630 -110.960 175.410 -110.450 ;
        RECT 176.120 -111.010 176.840 -110.520 ;
        RECT 177.960 -111.070 178.680 -110.580 ;
        RECT 86.810 -115.270 87.990 -114.080 ;
        RECT 103.390 -112.290 104.400 -111.440 ;
        RECT 119.320 -112.470 120.220 -111.720 ;
        RECT 136.290 -112.940 137.240 -112.320 ;
        RECT 173.230 -112.610 174.010 -112.100 ;
        RECT 174.660 -112.460 175.440 -111.950 ;
        RECT 176.150 -112.440 176.930 -111.930 ;
        RECT 177.940 -112.430 178.660 -111.940 ;
        RECT 103.400 -115.210 104.410 -114.360 ;
        RECT 119.350 -115.280 120.250 -114.530 ;
        RECT 136.130 -115.290 137.080 -114.670 ;
      LAYER met2 ;
        RECT 161.060 22.890 191.140 22.900 ;
        RECT 161.060 22.870 197.700 22.890 ;
        RECT 83.210 22.840 197.700 22.870 ;
        RECT 55.650 22.810 197.700 22.840 ;
        RECT 55.650 22.090 197.730 22.810 ;
        RECT 36.730 19.740 197.730 22.090 ;
        RECT 36.730 19.660 84.990 19.740 ;
        RECT 55.650 19.070 84.990 19.660 ;
        RECT 83.330 16.460 84.990 19.070 ;
        RECT 101.570 16.300 103.230 19.740 ;
        RECT 119.970 16.240 121.630 19.740 ;
        RECT 138.730 16.370 140.390 19.740 ;
        RECT 161.060 19.720 197.730 19.740 ;
        RECT 188.640 19.700 197.730 19.720 ;
        RECT 194.560 -9.060 197.730 19.700 ;
        RECT 194.600 -15.810 197.730 -9.060 ;
        RECT 86.320 -112.770 179.530 -110.000 ;
        RECT 86.520 -115.490 88.330 -112.770 ;
        RECT 103.000 -115.540 104.700 -112.770 ;
        RECT 118.950 -115.500 120.640 -112.770 ;
        RECT 135.930 -115.480 137.610 -112.770 ;
    END
  END C
  PIN VOUT
    ANTENNADIFFAREA 974.399963 ;
    PORT
      LAYER li1 ;
        RECT 86.250 17.580 86.420 57.620 ;
        RECT 87.830 17.580 88.000 57.620 ;
        RECT 89.410 17.580 89.580 57.620 ;
        RECT 90.990 17.580 91.160 57.620 ;
        RECT 92.570 17.580 92.740 57.620 ;
        RECT 94.150 17.580 94.320 57.620 ;
        RECT 104.480 17.420 104.650 57.460 ;
        RECT 106.060 17.420 106.230 57.460 ;
        RECT 107.640 17.420 107.810 57.460 ;
        RECT 109.220 17.420 109.390 57.460 ;
        RECT 110.800 17.420 110.970 57.460 ;
        RECT 112.380 17.420 112.550 57.460 ;
        RECT 122.880 17.370 123.050 57.410 ;
        RECT 124.460 17.370 124.630 57.410 ;
        RECT 126.040 17.370 126.210 57.410 ;
        RECT 127.620 17.370 127.790 57.410 ;
        RECT 129.200 17.370 129.370 57.410 ;
        RECT 130.780 17.370 130.950 57.410 ;
        RECT 141.650 17.520 141.820 57.560 ;
        RECT 143.230 17.520 143.400 57.560 ;
        RECT 144.810 17.520 144.980 57.560 ;
        RECT 146.390 17.520 146.560 57.560 ;
        RECT 147.970 17.520 148.140 57.560 ;
        RECT 149.550 17.520 149.720 57.560 ;
        RECT 60.440 -46.650 60.610 -6.610 ;
        RECT 62.020 -46.650 62.190 -6.610 ;
        RECT 63.600 -46.650 63.770 -6.610 ;
        RECT 65.180 -46.650 65.350 -6.610 ;
        RECT 66.760 -46.650 66.930 -6.610 ;
        RECT 68.340 -46.650 68.510 -6.610 ;
        RECT 77.490 -46.650 77.660 -6.610 ;
        RECT 79.070 -46.650 79.240 -6.610 ;
        RECT 80.650 -46.650 80.820 -6.610 ;
        RECT 82.230 -46.650 82.400 -6.610 ;
        RECT 83.810 -46.650 83.980 -6.610 ;
        RECT 85.390 -46.650 85.560 -6.610 ;
        RECT 103.330 -46.670 103.500 -6.630 ;
        RECT 104.910 -46.670 105.080 -6.630 ;
        RECT 106.490 -46.670 106.660 -6.630 ;
        RECT 108.070 -46.670 108.240 -6.630 ;
        RECT 109.650 -46.670 109.820 -6.630 ;
        RECT 111.230 -46.670 111.400 -6.630 ;
        RECT 124.350 -46.670 124.520 -6.630 ;
        RECT 125.930 -46.670 126.100 -6.630 ;
        RECT 127.510 -46.670 127.680 -6.630 ;
        RECT 129.090 -46.670 129.260 -6.630 ;
        RECT 130.670 -46.670 130.840 -6.630 ;
        RECT 132.250 -46.670 132.420 -6.630 ;
        RECT 148.420 -46.700 148.590 -6.660 ;
        RECT 150.000 -46.700 150.170 -6.660 ;
        RECT 151.580 -46.700 151.750 -6.660 ;
        RECT 153.160 -46.700 153.330 -6.660 ;
        RECT 154.740 -46.700 154.910 -6.660 ;
        RECT 156.320 -46.700 156.490 -6.660 ;
        RECT 166.490 -46.700 166.660 -6.660 ;
        RECT 168.070 -46.700 168.240 -6.660 ;
        RECT 169.650 -46.700 169.820 -6.660 ;
        RECT 171.230 -46.700 171.400 -6.660 ;
        RECT 172.810 -46.700 172.980 -6.660 ;
        RECT 174.390 -46.700 174.560 -6.660 ;
        RECT 89.530 -114.360 89.700 -74.320 ;
        RECT 91.110 -114.360 91.280 -74.320 ;
        RECT 92.690 -114.360 92.860 -74.320 ;
        RECT 94.270 -114.360 94.440 -74.320 ;
        RECT 95.850 -114.360 96.020 -74.320 ;
        RECT 97.430 -114.360 97.600 -74.320 ;
        RECT 105.920 -114.360 106.090 -74.320 ;
        RECT 107.500 -114.360 107.670 -74.320 ;
        RECT 109.080 -114.360 109.250 -74.320 ;
        RECT 110.660 -114.360 110.830 -74.320 ;
        RECT 112.240 -114.360 112.410 -74.320 ;
        RECT 113.820 -114.360 113.990 -74.320 ;
        RECT 121.880 -114.360 122.050 -74.320 ;
        RECT 123.460 -114.360 123.630 -74.320 ;
        RECT 125.040 -114.360 125.210 -74.320 ;
        RECT 126.620 -114.360 126.790 -74.320 ;
        RECT 128.200 -114.360 128.370 -74.320 ;
        RECT 129.780 -114.360 129.950 -74.320 ;
        RECT 138.870 -114.360 139.040 -74.320 ;
        RECT 140.450 -114.360 140.620 -74.320 ;
        RECT 142.030 -114.360 142.200 -74.320 ;
        RECT 143.610 -114.360 143.780 -74.320 ;
        RECT 145.190 -114.360 145.360 -74.320 ;
        RECT 146.770 -114.360 146.940 -74.320 ;
      LAYER mcon ;
        RECT 86.250 17.660 86.420 57.540 ;
        RECT 87.830 17.660 88.000 57.540 ;
        RECT 89.410 17.660 89.580 57.540 ;
        RECT 90.990 17.660 91.160 57.540 ;
        RECT 92.570 17.660 92.740 57.540 ;
        RECT 94.150 17.660 94.320 57.540 ;
        RECT 104.480 17.500 104.650 57.380 ;
        RECT 106.060 17.500 106.230 57.380 ;
        RECT 107.640 17.500 107.810 57.380 ;
        RECT 109.220 17.500 109.390 57.380 ;
        RECT 110.800 17.500 110.970 57.380 ;
        RECT 112.380 17.500 112.550 57.380 ;
        RECT 122.880 17.450 123.050 57.330 ;
        RECT 124.460 17.450 124.630 57.330 ;
        RECT 126.040 17.450 126.210 57.330 ;
        RECT 127.620 17.450 127.790 57.330 ;
        RECT 129.200 17.450 129.370 57.330 ;
        RECT 130.780 17.450 130.950 57.330 ;
        RECT 141.650 17.600 141.820 57.480 ;
        RECT 143.230 17.600 143.400 57.480 ;
        RECT 144.810 17.600 144.980 57.480 ;
        RECT 146.390 17.600 146.560 57.480 ;
        RECT 147.970 17.600 148.140 57.480 ;
        RECT 149.550 17.600 149.720 57.480 ;
        RECT 60.440 -46.570 60.610 -6.690 ;
        RECT 62.020 -46.570 62.190 -6.690 ;
        RECT 63.600 -46.570 63.770 -6.690 ;
        RECT 65.180 -46.570 65.350 -6.690 ;
        RECT 66.760 -46.570 66.930 -6.690 ;
        RECT 68.340 -46.570 68.510 -6.690 ;
        RECT 77.490 -46.570 77.660 -6.690 ;
        RECT 79.070 -46.570 79.240 -6.690 ;
        RECT 80.650 -46.570 80.820 -6.690 ;
        RECT 82.230 -46.570 82.400 -6.690 ;
        RECT 83.810 -46.570 83.980 -6.690 ;
        RECT 85.390 -46.570 85.560 -6.690 ;
        RECT 103.330 -46.590 103.500 -6.710 ;
        RECT 104.910 -46.590 105.080 -6.710 ;
        RECT 106.490 -46.590 106.660 -6.710 ;
        RECT 108.070 -46.590 108.240 -6.710 ;
        RECT 109.650 -46.590 109.820 -6.710 ;
        RECT 111.230 -46.590 111.400 -6.710 ;
        RECT 124.350 -46.590 124.520 -6.710 ;
        RECT 125.930 -46.590 126.100 -6.710 ;
        RECT 127.510 -46.590 127.680 -6.710 ;
        RECT 129.090 -46.590 129.260 -6.710 ;
        RECT 130.670 -46.590 130.840 -6.710 ;
        RECT 132.250 -46.590 132.420 -6.710 ;
        RECT 148.420 -46.620 148.590 -6.740 ;
        RECT 150.000 -46.620 150.170 -6.740 ;
        RECT 151.580 -46.620 151.750 -6.740 ;
        RECT 153.160 -46.620 153.330 -6.740 ;
        RECT 154.740 -46.620 154.910 -6.740 ;
        RECT 156.320 -46.620 156.490 -6.740 ;
        RECT 166.490 -46.620 166.660 -6.740 ;
        RECT 168.070 -46.620 168.240 -6.740 ;
        RECT 169.650 -46.620 169.820 -6.740 ;
        RECT 171.230 -46.620 171.400 -6.740 ;
        RECT 172.810 -46.620 172.980 -6.740 ;
        RECT 174.390 -46.620 174.560 -6.740 ;
        RECT 89.530 -114.280 89.700 -74.400 ;
        RECT 91.110 -114.280 91.280 -74.400 ;
        RECT 92.690 -114.280 92.860 -74.400 ;
        RECT 94.270 -114.280 94.440 -74.400 ;
        RECT 95.850 -114.280 96.020 -74.400 ;
        RECT 97.430 -114.280 97.600 -74.400 ;
        RECT 105.920 -114.280 106.090 -74.400 ;
        RECT 107.500 -114.280 107.670 -74.400 ;
        RECT 109.080 -114.280 109.250 -74.400 ;
        RECT 110.660 -114.280 110.830 -74.400 ;
        RECT 112.240 -114.280 112.410 -74.400 ;
        RECT 113.820 -114.280 113.990 -74.400 ;
        RECT 121.880 -114.280 122.050 -74.400 ;
        RECT 123.460 -114.280 123.630 -74.400 ;
        RECT 125.040 -114.280 125.210 -74.400 ;
        RECT 126.620 -114.280 126.790 -74.400 ;
        RECT 128.200 -114.280 128.370 -74.400 ;
        RECT 129.780 -114.280 129.950 -74.400 ;
        RECT 138.870 -114.280 139.040 -74.400 ;
        RECT 140.450 -114.280 140.620 -74.400 ;
        RECT 142.030 -114.280 142.200 -74.400 ;
        RECT 143.610 -114.280 143.780 -74.400 ;
        RECT 145.190 -114.280 145.360 -74.400 ;
        RECT 146.770 -114.280 146.940 -74.400 ;
      LAYER met1 ;
        RECT 86.220 18.420 86.450 57.600 ;
        RECT 86.160 17.920 86.590 18.420 ;
        RECT 87.800 18.410 88.030 57.600 ;
        RECT 89.380 18.410 89.610 57.600 ;
        RECT 90.960 18.410 91.190 57.600 ;
        RECT 92.540 18.410 92.770 57.600 ;
        RECT 86.220 17.600 86.450 17.920 ;
        RECT 87.740 17.910 88.170 18.410 ;
        RECT 89.330 17.910 89.760 18.410 ;
        RECT 90.880 17.910 91.310 18.410 ;
        RECT 92.410 17.910 92.840 18.410 ;
        RECT 94.120 18.350 94.350 57.600 ;
        RECT 87.800 17.600 88.030 17.910 ;
        RECT 89.380 17.600 89.610 17.910 ;
        RECT 90.960 17.600 91.190 17.910 ;
        RECT 92.540 17.600 92.770 17.910 ;
        RECT 94.050 17.850 94.480 18.350 ;
        RECT 104.450 18.260 104.680 57.440 ;
        RECT 94.120 17.600 94.350 17.850 ;
        RECT 104.390 17.760 104.820 18.260 ;
        RECT 106.030 18.250 106.260 57.440 ;
        RECT 107.610 18.250 107.840 57.440 ;
        RECT 109.190 18.250 109.420 57.440 ;
        RECT 110.770 18.250 111.000 57.440 ;
        RECT 104.450 17.440 104.680 17.760 ;
        RECT 105.970 17.750 106.400 18.250 ;
        RECT 107.560 17.750 107.990 18.250 ;
        RECT 109.110 17.750 109.540 18.250 ;
        RECT 110.640 17.750 111.070 18.250 ;
        RECT 112.350 18.190 112.580 57.440 ;
        RECT 122.850 18.210 123.080 57.390 ;
        RECT 106.030 17.440 106.260 17.750 ;
        RECT 107.610 17.440 107.840 17.750 ;
        RECT 109.190 17.440 109.420 17.750 ;
        RECT 110.770 17.440 111.000 17.750 ;
        RECT 112.280 17.690 112.710 18.190 ;
        RECT 122.790 17.710 123.220 18.210 ;
        RECT 124.430 18.200 124.660 57.390 ;
        RECT 126.010 18.200 126.240 57.390 ;
        RECT 127.590 18.200 127.820 57.390 ;
        RECT 129.170 18.200 129.400 57.390 ;
        RECT 112.350 17.440 112.580 17.690 ;
        RECT 122.850 17.390 123.080 17.710 ;
        RECT 124.370 17.700 124.800 18.200 ;
        RECT 125.960 17.700 126.390 18.200 ;
        RECT 127.510 17.700 127.940 18.200 ;
        RECT 129.040 17.700 129.470 18.200 ;
        RECT 130.750 18.140 130.980 57.390 ;
        RECT 141.620 18.360 141.850 57.540 ;
        RECT 124.430 17.390 124.660 17.700 ;
        RECT 126.010 17.390 126.240 17.700 ;
        RECT 127.590 17.390 127.820 17.700 ;
        RECT 129.170 17.390 129.400 17.700 ;
        RECT 130.680 17.640 131.110 18.140 ;
        RECT 141.560 17.860 141.990 18.360 ;
        RECT 143.200 18.350 143.430 57.540 ;
        RECT 144.780 18.350 145.010 57.540 ;
        RECT 146.360 18.350 146.590 57.540 ;
        RECT 147.940 18.350 148.170 57.540 ;
        RECT 130.750 17.390 130.980 17.640 ;
        RECT 141.620 17.540 141.850 17.860 ;
        RECT 143.140 17.850 143.570 18.350 ;
        RECT 144.730 17.850 145.160 18.350 ;
        RECT 146.280 17.850 146.710 18.350 ;
        RECT 147.810 17.850 148.240 18.350 ;
        RECT 149.520 18.290 149.750 57.540 ;
        RECT 143.200 17.540 143.430 17.850 ;
        RECT 144.780 17.540 145.010 17.850 ;
        RECT 146.360 17.540 146.590 17.850 ;
        RECT 147.940 17.540 148.170 17.850 ;
        RECT 149.450 17.790 149.880 18.290 ;
        RECT 149.520 17.540 149.750 17.790 ;
        RECT 86.030 15.600 138.640 15.630 ;
        RECT 86.030 11.740 193.120 15.600 ;
        RECT 120.200 11.710 193.120 11.740 ;
        RECT 60.410 -45.810 60.640 -6.630 ;
        RECT 60.350 -46.310 60.780 -45.810 ;
        RECT 61.990 -45.820 62.220 -6.630 ;
        RECT 63.570 -45.820 63.800 -6.630 ;
        RECT 65.150 -45.820 65.380 -6.630 ;
        RECT 66.730 -45.820 66.960 -6.630 ;
        RECT 60.410 -46.630 60.640 -46.310 ;
        RECT 61.930 -46.320 62.360 -45.820 ;
        RECT 63.520 -46.320 63.950 -45.820 ;
        RECT 65.070 -46.320 65.500 -45.820 ;
        RECT 66.600 -46.320 67.030 -45.820 ;
        RECT 68.310 -45.880 68.540 -6.630 ;
        RECT 77.460 -45.810 77.690 -6.630 ;
        RECT 61.990 -46.630 62.220 -46.320 ;
        RECT 63.570 -46.630 63.800 -46.320 ;
        RECT 65.150 -46.630 65.380 -46.320 ;
        RECT 66.730 -46.630 66.960 -46.320 ;
        RECT 68.240 -46.380 68.670 -45.880 ;
        RECT 77.400 -46.310 77.830 -45.810 ;
        RECT 79.040 -45.820 79.270 -6.630 ;
        RECT 80.620 -45.820 80.850 -6.630 ;
        RECT 82.200 -45.820 82.430 -6.630 ;
        RECT 83.780 -45.820 84.010 -6.630 ;
        RECT 68.310 -46.630 68.540 -46.380 ;
        RECT 77.460 -46.630 77.690 -46.310 ;
        RECT 78.980 -46.320 79.410 -45.820 ;
        RECT 80.570 -46.320 81.000 -45.820 ;
        RECT 82.120 -46.320 82.550 -45.820 ;
        RECT 83.650 -46.320 84.080 -45.820 ;
        RECT 85.360 -45.880 85.590 -6.630 ;
        RECT 103.300 -45.830 103.530 -6.650 ;
        RECT 79.040 -46.630 79.270 -46.320 ;
        RECT 80.620 -46.630 80.850 -46.320 ;
        RECT 82.200 -46.630 82.430 -46.320 ;
        RECT 83.780 -46.630 84.010 -46.320 ;
        RECT 85.290 -46.380 85.720 -45.880 ;
        RECT 103.240 -46.330 103.670 -45.830 ;
        RECT 104.880 -45.840 105.110 -6.650 ;
        RECT 106.460 -45.840 106.690 -6.650 ;
        RECT 108.040 -45.840 108.270 -6.650 ;
        RECT 109.620 -45.840 109.850 -6.650 ;
        RECT 85.360 -46.630 85.590 -46.380 ;
        RECT 103.300 -46.650 103.530 -46.330 ;
        RECT 104.820 -46.340 105.250 -45.840 ;
        RECT 106.410 -46.340 106.840 -45.840 ;
        RECT 107.960 -46.340 108.390 -45.840 ;
        RECT 109.490 -46.340 109.920 -45.840 ;
        RECT 111.200 -45.900 111.430 -6.650 ;
        RECT 124.320 -45.830 124.550 -6.650 ;
        RECT 104.880 -46.650 105.110 -46.340 ;
        RECT 106.460 -46.650 106.690 -46.340 ;
        RECT 108.040 -46.650 108.270 -46.340 ;
        RECT 109.620 -46.650 109.850 -46.340 ;
        RECT 111.130 -46.400 111.560 -45.900 ;
        RECT 124.260 -46.330 124.690 -45.830 ;
        RECT 125.900 -45.840 126.130 -6.650 ;
        RECT 127.480 -45.840 127.710 -6.650 ;
        RECT 129.060 -45.840 129.290 -6.650 ;
        RECT 130.640 -45.840 130.870 -6.650 ;
        RECT 111.200 -46.650 111.430 -46.400 ;
        RECT 124.320 -46.650 124.550 -46.330 ;
        RECT 125.840 -46.340 126.270 -45.840 ;
        RECT 127.430 -46.340 127.860 -45.840 ;
        RECT 128.980 -46.340 129.410 -45.840 ;
        RECT 130.510 -46.340 130.940 -45.840 ;
        RECT 132.220 -45.900 132.450 -6.650 ;
        RECT 148.390 -45.860 148.620 -6.680 ;
        RECT 125.900 -46.650 126.130 -46.340 ;
        RECT 127.480 -46.650 127.710 -46.340 ;
        RECT 129.060 -46.650 129.290 -46.340 ;
        RECT 130.640 -46.650 130.870 -46.340 ;
        RECT 132.150 -46.400 132.580 -45.900 ;
        RECT 148.330 -46.360 148.760 -45.860 ;
        RECT 149.970 -45.870 150.200 -6.680 ;
        RECT 151.550 -45.870 151.780 -6.680 ;
        RECT 153.130 -45.870 153.360 -6.680 ;
        RECT 154.710 -45.870 154.940 -6.680 ;
        RECT 132.220 -46.650 132.450 -46.400 ;
        RECT 148.390 -46.680 148.620 -46.360 ;
        RECT 149.910 -46.370 150.340 -45.870 ;
        RECT 151.500 -46.370 151.930 -45.870 ;
        RECT 153.050 -46.370 153.480 -45.870 ;
        RECT 154.580 -46.370 155.010 -45.870 ;
        RECT 156.290 -45.930 156.520 -6.680 ;
        RECT 166.460 -45.860 166.690 -6.680 ;
        RECT 149.970 -46.680 150.200 -46.370 ;
        RECT 151.550 -46.680 151.780 -46.370 ;
        RECT 153.130 -46.680 153.360 -46.370 ;
        RECT 154.710 -46.680 154.940 -46.370 ;
        RECT 156.220 -46.430 156.650 -45.930 ;
        RECT 166.400 -46.360 166.830 -45.860 ;
        RECT 168.040 -45.870 168.270 -6.680 ;
        RECT 169.620 -45.870 169.850 -6.680 ;
        RECT 171.200 -45.870 171.430 -6.680 ;
        RECT 172.780 -45.870 173.010 -6.680 ;
        RECT 156.290 -46.680 156.520 -46.430 ;
        RECT 166.460 -46.680 166.690 -46.360 ;
        RECT 167.980 -46.370 168.410 -45.870 ;
        RECT 169.570 -46.370 170.000 -45.870 ;
        RECT 171.120 -46.370 171.550 -45.870 ;
        RECT 172.650 -46.370 173.080 -45.870 ;
        RECT 174.360 -45.930 174.590 -6.680 ;
        RECT 168.040 -46.680 168.270 -46.370 ;
        RECT 169.620 -46.680 169.850 -46.370 ;
        RECT 171.200 -46.680 171.430 -46.370 ;
        RECT 172.780 -46.680 173.010 -46.370 ;
        RECT 174.290 -46.430 174.720 -45.930 ;
        RECT 174.360 -46.680 174.590 -46.430 ;
        RECT 59.540 -48.480 195.600 -48.470 ;
        RECT 200.070 -48.480 216.920 -48.470 ;
        RECT 59.540 -52.320 216.920 -48.480 ;
        RECT 193.930 -52.330 216.920 -52.320 ;
        RECT 193.930 -52.350 201.240 -52.330 ;
        RECT 89.500 -113.520 89.730 -74.340 ;
        RECT 89.440 -114.020 89.870 -113.520 ;
        RECT 91.080 -113.530 91.310 -74.340 ;
        RECT 92.660 -113.530 92.890 -74.340 ;
        RECT 94.240 -113.530 94.470 -74.340 ;
        RECT 95.820 -113.530 96.050 -74.340 ;
        RECT 89.500 -114.340 89.730 -114.020 ;
        RECT 91.020 -114.030 91.450 -113.530 ;
        RECT 92.610 -114.030 93.040 -113.530 ;
        RECT 94.160 -114.030 94.590 -113.530 ;
        RECT 95.690 -114.030 96.120 -113.530 ;
        RECT 97.400 -113.590 97.630 -74.340 ;
        RECT 105.890 -113.520 106.120 -74.340 ;
        RECT 91.080 -114.340 91.310 -114.030 ;
        RECT 92.660 -114.340 92.890 -114.030 ;
        RECT 94.240 -114.340 94.470 -114.030 ;
        RECT 95.820 -114.340 96.050 -114.030 ;
        RECT 97.330 -114.090 97.760 -113.590 ;
        RECT 105.830 -114.020 106.260 -113.520 ;
        RECT 107.470 -113.530 107.700 -74.340 ;
        RECT 109.050 -113.530 109.280 -74.340 ;
        RECT 110.630 -113.530 110.860 -74.340 ;
        RECT 112.210 -113.530 112.440 -74.340 ;
        RECT 97.400 -114.340 97.630 -114.090 ;
        RECT 105.890 -114.340 106.120 -114.020 ;
        RECT 107.410 -114.030 107.840 -113.530 ;
        RECT 109.000 -114.030 109.430 -113.530 ;
        RECT 110.550 -114.030 110.980 -113.530 ;
        RECT 112.080 -114.030 112.510 -113.530 ;
        RECT 113.790 -113.590 114.020 -74.340 ;
        RECT 121.850 -113.520 122.080 -74.340 ;
        RECT 107.470 -114.340 107.700 -114.030 ;
        RECT 109.050 -114.340 109.280 -114.030 ;
        RECT 110.630 -114.340 110.860 -114.030 ;
        RECT 112.210 -114.340 112.440 -114.030 ;
        RECT 113.720 -114.090 114.150 -113.590 ;
        RECT 121.790 -114.020 122.220 -113.520 ;
        RECT 123.430 -113.530 123.660 -74.340 ;
        RECT 125.010 -113.530 125.240 -74.340 ;
        RECT 126.590 -113.530 126.820 -74.340 ;
        RECT 128.170 -113.530 128.400 -74.340 ;
        RECT 113.790 -114.340 114.020 -114.090 ;
        RECT 121.850 -114.340 122.080 -114.020 ;
        RECT 123.370 -114.030 123.800 -113.530 ;
        RECT 124.960 -114.030 125.390 -113.530 ;
        RECT 126.510 -114.030 126.940 -113.530 ;
        RECT 128.040 -114.030 128.470 -113.530 ;
        RECT 129.750 -113.590 129.980 -74.340 ;
        RECT 138.840 -113.520 139.070 -74.340 ;
        RECT 123.430 -114.340 123.660 -114.030 ;
        RECT 125.010 -114.340 125.240 -114.030 ;
        RECT 126.590 -114.340 126.820 -114.030 ;
        RECT 128.170 -114.340 128.400 -114.030 ;
        RECT 129.680 -114.090 130.110 -113.590 ;
        RECT 138.780 -114.020 139.210 -113.520 ;
        RECT 140.420 -113.530 140.650 -74.340 ;
        RECT 142.000 -113.530 142.230 -74.340 ;
        RECT 143.580 -113.530 143.810 -74.340 ;
        RECT 145.160 -113.530 145.390 -74.340 ;
        RECT 129.750 -114.340 129.980 -114.090 ;
        RECT 138.840 -114.340 139.070 -114.020 ;
        RECT 140.360 -114.030 140.790 -113.530 ;
        RECT 141.950 -114.030 142.380 -113.530 ;
        RECT 143.500 -114.030 143.930 -113.530 ;
        RECT 145.030 -114.030 145.460 -113.530 ;
        RECT 146.740 -113.590 146.970 -74.340 ;
        RECT 140.420 -114.340 140.650 -114.030 ;
        RECT 142.000 -114.340 142.230 -114.030 ;
        RECT 143.580 -114.340 143.810 -114.030 ;
        RECT 145.160 -114.340 145.390 -114.030 ;
        RECT 146.670 -114.090 147.100 -113.590 ;
        RECT 146.740 -114.340 146.970 -114.090 ;
        RECT 89.310 -119.770 190.440 -115.970 ;
      LAYER via ;
        RECT 86.230 18.000 86.520 18.330 ;
        RECT 87.810 17.990 88.100 18.320 ;
        RECT 89.400 17.990 89.690 18.320 ;
        RECT 90.950 17.990 91.240 18.320 ;
        RECT 92.480 17.990 92.770 18.320 ;
        RECT 94.120 17.930 94.410 18.260 ;
        RECT 104.460 17.840 104.750 18.170 ;
        RECT 106.040 17.830 106.330 18.160 ;
        RECT 107.630 17.830 107.920 18.160 ;
        RECT 109.180 17.830 109.470 18.160 ;
        RECT 110.710 17.830 111.000 18.160 ;
        RECT 112.350 17.770 112.640 18.100 ;
        RECT 122.860 17.790 123.150 18.120 ;
        RECT 124.440 17.780 124.730 18.110 ;
        RECT 126.030 17.780 126.320 18.110 ;
        RECT 127.580 17.780 127.870 18.110 ;
        RECT 129.110 17.780 129.400 18.110 ;
        RECT 130.750 17.720 131.040 18.050 ;
        RECT 141.630 17.940 141.920 18.270 ;
        RECT 143.210 17.930 143.500 18.260 ;
        RECT 144.800 17.930 145.090 18.260 ;
        RECT 146.350 17.930 146.640 18.260 ;
        RECT 147.880 17.930 148.170 18.260 ;
        RECT 149.520 17.870 149.810 18.200 ;
        RECT 88.310 13.380 92.410 14.640 ;
        RECT 106.540 13.220 110.640 14.480 ;
        RECT 124.940 13.170 129.040 14.430 ;
        RECT 143.710 13.320 147.810 14.580 ;
        RECT 184.860 14.460 185.890 15.320 ;
        RECT 187.270 14.450 188.300 15.310 ;
        RECT 190.460 14.520 191.490 15.380 ;
        RECT 184.850 13.230 185.880 14.090 ;
        RECT 187.230 13.210 188.260 14.070 ;
        RECT 190.440 13.280 191.470 14.140 ;
        RECT 184.830 12.110 185.860 12.970 ;
        RECT 187.270 12.090 188.300 12.950 ;
        RECT 190.480 12.130 191.510 12.990 ;
        RECT 60.420 -46.230 60.710 -45.900 ;
        RECT 62.000 -46.240 62.290 -45.910 ;
        RECT 63.590 -46.240 63.880 -45.910 ;
        RECT 65.140 -46.240 65.430 -45.910 ;
        RECT 66.670 -46.240 66.960 -45.910 ;
        RECT 68.310 -46.300 68.600 -45.970 ;
        RECT 77.470 -46.230 77.760 -45.900 ;
        RECT 79.050 -46.240 79.340 -45.910 ;
        RECT 80.640 -46.240 80.930 -45.910 ;
        RECT 82.190 -46.240 82.480 -45.910 ;
        RECT 83.720 -46.240 84.010 -45.910 ;
        RECT 85.360 -46.300 85.650 -45.970 ;
        RECT 103.310 -46.250 103.600 -45.920 ;
        RECT 104.890 -46.260 105.180 -45.930 ;
        RECT 106.480 -46.260 106.770 -45.930 ;
        RECT 108.030 -46.260 108.320 -45.930 ;
        RECT 109.560 -46.260 109.850 -45.930 ;
        RECT 111.200 -46.320 111.490 -45.990 ;
        RECT 124.330 -46.250 124.620 -45.920 ;
        RECT 125.910 -46.260 126.200 -45.930 ;
        RECT 127.500 -46.260 127.790 -45.930 ;
        RECT 129.050 -46.260 129.340 -45.930 ;
        RECT 130.580 -46.260 130.870 -45.930 ;
        RECT 132.220 -46.320 132.510 -45.990 ;
        RECT 148.400 -46.280 148.690 -45.950 ;
        RECT 149.980 -46.290 150.270 -45.960 ;
        RECT 151.570 -46.290 151.860 -45.960 ;
        RECT 153.120 -46.290 153.410 -45.960 ;
        RECT 154.650 -46.290 154.940 -45.960 ;
        RECT 156.290 -46.350 156.580 -46.020 ;
        RECT 166.470 -46.280 166.760 -45.950 ;
        RECT 168.050 -46.290 168.340 -45.960 ;
        RECT 169.640 -46.290 169.930 -45.960 ;
        RECT 171.190 -46.290 171.480 -45.960 ;
        RECT 172.720 -46.290 173.010 -45.960 ;
        RECT 174.360 -46.350 174.650 -46.020 ;
        RECT 62.500 -50.850 66.600 -49.590 ;
        RECT 79.550 -50.850 83.650 -49.590 ;
        RECT 185.380 -49.600 186.380 -48.840 ;
        RECT 188.380 -49.580 189.380 -48.820 ;
        RECT 190.810 -49.590 191.810 -48.830 ;
        RECT 105.390 -50.870 109.490 -49.610 ;
        RECT 126.410 -50.870 130.510 -49.610 ;
        RECT 150.480 -50.900 154.580 -49.640 ;
        RECT 168.550 -50.900 172.650 -49.640 ;
        RECT 185.390 -50.840 186.390 -50.080 ;
        RECT 188.310 -50.720 189.310 -49.960 ;
        RECT 190.860 -50.770 191.860 -50.010 ;
        RECT 185.400 -51.970 186.400 -51.210 ;
        RECT 188.360 -51.980 189.360 -51.220 ;
        RECT 190.900 -51.990 191.900 -51.230 ;
        RECT 89.510 -113.940 89.800 -113.610 ;
        RECT 91.090 -113.950 91.380 -113.620 ;
        RECT 92.680 -113.950 92.970 -113.620 ;
        RECT 94.230 -113.950 94.520 -113.620 ;
        RECT 95.760 -113.950 96.050 -113.620 ;
        RECT 97.400 -114.010 97.690 -113.680 ;
        RECT 105.900 -113.940 106.190 -113.610 ;
        RECT 107.480 -113.950 107.770 -113.620 ;
        RECT 109.070 -113.950 109.360 -113.620 ;
        RECT 110.620 -113.950 110.910 -113.620 ;
        RECT 112.150 -113.950 112.440 -113.620 ;
        RECT 113.790 -114.010 114.080 -113.680 ;
        RECT 121.860 -113.940 122.150 -113.610 ;
        RECT 123.440 -113.950 123.730 -113.620 ;
        RECT 125.030 -113.950 125.320 -113.620 ;
        RECT 126.580 -113.950 126.870 -113.620 ;
        RECT 128.110 -113.950 128.400 -113.620 ;
        RECT 129.750 -114.010 130.040 -113.680 ;
        RECT 138.850 -113.940 139.140 -113.610 ;
        RECT 140.430 -113.950 140.720 -113.620 ;
        RECT 142.020 -113.950 142.310 -113.620 ;
        RECT 143.570 -113.950 143.860 -113.620 ;
        RECT 145.100 -113.950 145.390 -113.620 ;
        RECT 146.740 -114.010 147.030 -113.680 ;
        RECT 181.380 -117.130 182.210 -116.400 ;
        RECT 185.110 -117.160 185.940 -116.430 ;
        RECT 187.590 -117.020 188.420 -116.290 ;
        RECT 189.360 -117.010 190.190 -116.280 ;
        RECT 91.590 -118.560 95.690 -117.300 ;
        RECT 107.980 -118.560 112.080 -117.300 ;
        RECT 123.940 -118.560 128.040 -117.300 ;
        RECT 140.930 -118.560 145.030 -117.300 ;
        RECT 181.380 -118.220 182.210 -117.490 ;
        RECT 185.170 -118.360 186.000 -117.630 ;
        RECT 187.670 -118.400 188.500 -117.670 ;
        RECT 189.360 -118.390 190.190 -117.660 ;
        RECT 181.320 -119.450 182.150 -118.720 ;
        RECT 185.110 -119.530 185.940 -118.800 ;
        RECT 187.680 -119.610 188.510 -118.880 ;
        RECT 189.380 -119.540 190.210 -118.810 ;
      LAYER met2 ;
        RECT 86.160 15.900 86.590 18.420 ;
        RECT 87.740 18.010 88.170 18.410 ;
        RECT 87.740 17.910 88.180 18.010 ;
        RECT 89.330 17.970 89.760 18.410 ;
        RECT 89.330 17.910 89.770 17.970 ;
        RECT 87.750 15.900 88.180 17.910 ;
        RECT 89.340 15.900 89.770 17.910 ;
        RECT 90.880 15.900 91.310 18.410 ;
        RECT 92.410 15.900 92.840 18.410 ;
        RECT 94.050 15.900 94.480 18.350 ;
        RECT 86.110 15.630 94.490 15.900 ;
        RECT 104.390 15.740 104.820 18.260 ;
        RECT 105.970 17.850 106.400 18.250 ;
        RECT 105.970 17.750 106.410 17.850 ;
        RECT 107.560 17.810 107.990 18.250 ;
        RECT 107.560 17.750 108.000 17.810 ;
        RECT 105.980 15.740 106.410 17.750 ;
        RECT 107.570 15.740 108.000 17.750 ;
        RECT 109.110 15.740 109.540 18.250 ;
        RECT 110.640 15.740 111.070 18.250 ;
        RECT 112.280 15.740 112.710 18.190 ;
        RECT 104.340 15.630 112.720 15.740 ;
        RECT 122.790 15.690 123.220 18.210 ;
        RECT 124.370 17.800 124.800 18.200 ;
        RECT 124.370 17.700 124.810 17.800 ;
        RECT 125.960 17.760 126.390 18.200 ;
        RECT 125.960 17.700 126.400 17.760 ;
        RECT 124.380 15.690 124.810 17.700 ;
        RECT 125.970 15.690 126.400 17.700 ;
        RECT 127.510 15.690 127.940 18.200 ;
        RECT 129.040 15.690 129.470 18.200 ;
        RECT 130.680 15.690 131.110 18.140 ;
        RECT 141.560 15.840 141.990 18.360 ;
        RECT 143.140 17.950 143.570 18.350 ;
        RECT 143.140 17.850 143.580 17.950 ;
        RECT 144.730 17.910 145.160 18.350 ;
        RECT 144.730 17.850 145.170 17.910 ;
        RECT 143.150 15.840 143.580 17.850 ;
        RECT 144.740 15.840 145.170 17.850 ;
        RECT 146.280 15.840 146.710 18.350 ;
        RECT 147.810 15.840 148.240 18.350 ;
        RECT 149.450 15.840 149.880 18.290 ;
        RECT 122.740 15.630 131.120 15.690 ;
        RECT 86.030 15.600 138.640 15.630 ;
        RECT 141.510 15.600 149.890 15.840 ;
        RECT 86.030 11.740 193.210 15.600 ;
        RECT 120.200 11.710 193.210 11.740 ;
        RECT 60.350 -48.330 60.780 -45.810 ;
        RECT 61.930 -46.220 62.360 -45.820 ;
        RECT 61.930 -46.320 62.370 -46.220 ;
        RECT 63.520 -46.260 63.950 -45.820 ;
        RECT 63.520 -46.320 63.960 -46.260 ;
        RECT 61.940 -48.330 62.370 -46.320 ;
        RECT 63.530 -48.330 63.960 -46.320 ;
        RECT 65.070 -48.330 65.500 -45.820 ;
        RECT 66.600 -48.330 67.030 -45.820 ;
        RECT 68.240 -48.330 68.670 -45.880 ;
        RECT 77.400 -48.330 77.830 -45.810 ;
        RECT 78.980 -46.220 79.410 -45.820 ;
        RECT 78.980 -46.320 79.420 -46.220 ;
        RECT 80.570 -46.260 81.000 -45.820 ;
        RECT 80.570 -46.320 81.010 -46.260 ;
        RECT 78.990 -48.330 79.420 -46.320 ;
        RECT 80.580 -48.330 81.010 -46.320 ;
        RECT 82.120 -48.330 82.550 -45.820 ;
        RECT 83.650 -48.330 84.080 -45.820 ;
        RECT 85.290 -48.330 85.720 -45.880 ;
        RECT 60.300 -48.470 68.680 -48.330 ;
        RECT 77.350 -48.470 85.730 -48.330 ;
        RECT 103.240 -48.350 103.670 -45.830 ;
        RECT 104.820 -46.240 105.250 -45.840 ;
        RECT 104.820 -46.340 105.260 -46.240 ;
        RECT 106.410 -46.280 106.840 -45.840 ;
        RECT 106.410 -46.340 106.850 -46.280 ;
        RECT 104.830 -48.350 105.260 -46.340 ;
        RECT 106.420 -48.350 106.850 -46.340 ;
        RECT 107.960 -48.350 108.390 -45.840 ;
        RECT 109.490 -48.350 109.920 -45.840 ;
        RECT 111.130 -48.350 111.560 -45.900 ;
        RECT 124.260 -48.350 124.690 -45.830 ;
        RECT 125.840 -46.240 126.270 -45.840 ;
        RECT 125.840 -46.340 126.280 -46.240 ;
        RECT 127.430 -46.280 127.860 -45.840 ;
        RECT 127.430 -46.340 127.870 -46.280 ;
        RECT 125.850 -48.350 126.280 -46.340 ;
        RECT 127.440 -48.350 127.870 -46.340 ;
        RECT 128.980 -48.350 129.410 -45.840 ;
        RECT 130.510 -48.350 130.940 -45.840 ;
        RECT 132.150 -48.350 132.580 -45.900 ;
        RECT 103.190 -48.470 111.570 -48.350 ;
        RECT 124.210 -48.470 132.590 -48.350 ;
        RECT 148.330 -48.380 148.760 -45.860 ;
        RECT 149.910 -46.270 150.340 -45.870 ;
        RECT 149.910 -46.370 150.350 -46.270 ;
        RECT 151.500 -46.310 151.930 -45.870 ;
        RECT 151.500 -46.370 151.940 -46.310 ;
        RECT 149.920 -48.380 150.350 -46.370 ;
        RECT 151.510 -48.380 151.940 -46.370 ;
        RECT 153.050 -48.380 153.480 -45.870 ;
        RECT 154.580 -48.380 155.010 -45.870 ;
        RECT 156.220 -48.380 156.650 -45.930 ;
        RECT 166.400 -48.380 166.830 -45.860 ;
        RECT 167.980 -46.270 168.410 -45.870 ;
        RECT 167.980 -46.370 168.420 -46.270 ;
        RECT 169.570 -46.310 170.000 -45.870 ;
        RECT 169.570 -46.370 170.010 -46.310 ;
        RECT 167.990 -48.380 168.420 -46.370 ;
        RECT 169.580 -48.380 170.010 -46.370 ;
        RECT 171.120 -48.380 171.550 -45.870 ;
        RECT 172.650 -48.380 173.080 -45.870 ;
        RECT 174.290 -48.380 174.720 -45.930 ;
        RECT 148.280 -48.470 156.660 -48.380 ;
        RECT 166.350 -48.470 174.730 -48.380 ;
        RECT 184.370 -48.470 193.210 11.710 ;
        RECT 59.540 -48.480 195.600 -48.470 ;
        RECT 200.070 -48.480 216.920 -48.470 ;
        RECT 59.540 -52.320 216.920 -48.480 ;
        RECT 184.370 -63.070 193.210 -52.320 ;
        RECT 193.930 -52.330 216.920 -52.320 ;
        RECT 193.930 -52.350 201.240 -52.330 ;
        RECT 184.360 -68.530 193.210 -63.070 ;
        RECT 89.440 -115.970 89.870 -113.520 ;
        RECT 91.020 -113.930 91.450 -113.530 ;
        RECT 91.020 -114.030 91.460 -113.930 ;
        RECT 92.610 -113.970 93.040 -113.530 ;
        RECT 92.610 -114.030 93.050 -113.970 ;
        RECT 91.030 -115.970 91.460 -114.030 ;
        RECT 92.620 -115.970 93.050 -114.030 ;
        RECT 94.160 -115.970 94.590 -113.530 ;
        RECT 95.690 -115.970 96.120 -113.530 ;
        RECT 97.330 -115.970 97.760 -113.590 ;
        RECT 105.830 -115.970 106.260 -113.520 ;
        RECT 107.410 -113.930 107.840 -113.530 ;
        RECT 107.410 -114.030 107.850 -113.930 ;
        RECT 109.000 -113.970 109.430 -113.530 ;
        RECT 109.000 -114.030 109.440 -113.970 ;
        RECT 107.420 -115.970 107.850 -114.030 ;
        RECT 109.010 -115.970 109.440 -114.030 ;
        RECT 110.550 -115.970 110.980 -113.530 ;
        RECT 112.080 -115.970 112.510 -113.530 ;
        RECT 113.720 -115.970 114.150 -113.590 ;
        RECT 121.790 -115.970 122.220 -113.520 ;
        RECT 123.370 -113.930 123.800 -113.530 ;
        RECT 123.370 -114.030 123.810 -113.930 ;
        RECT 124.960 -113.970 125.390 -113.530 ;
        RECT 124.960 -114.030 125.400 -113.970 ;
        RECT 123.380 -115.970 123.810 -114.030 ;
        RECT 124.970 -115.970 125.400 -114.030 ;
        RECT 126.510 -115.970 126.940 -113.530 ;
        RECT 128.040 -115.970 128.470 -113.530 ;
        RECT 129.680 -115.970 130.110 -113.590 ;
        RECT 138.780 -115.970 139.210 -113.520 ;
        RECT 140.360 -113.930 140.790 -113.530 ;
        RECT 140.360 -114.030 140.800 -113.930 ;
        RECT 141.950 -113.970 142.380 -113.530 ;
        RECT 141.950 -114.030 142.390 -113.970 ;
        RECT 140.370 -115.970 140.800 -114.030 ;
        RECT 141.960 -115.970 142.390 -114.030 ;
        RECT 143.500 -115.970 143.930 -113.530 ;
        RECT 145.030 -115.970 145.460 -113.530 ;
        RECT 146.670 -115.970 147.100 -113.590 ;
        RECT 184.370 -115.970 193.210 -68.530 ;
        RECT 89.310 -119.770 193.210 -115.970 ;
        RECT 184.370 -119.970 193.210 -119.770 ;
    END
  END VOUT
  PIN VDD
    USE POWER ;
    ANTENNADIFFAREA 106.574997 ;
    PORT
      LAYER nwell ;
        RECT 61.165 59.525 74.135 64.105 ;
        RECT 86.500 60.720 94.470 63.800 ;
        RECT 104.730 60.560 112.700 63.640 ;
        RECT 123.130 60.510 131.100 63.590 ;
        RECT 141.900 60.660 149.870 63.740 ;
        RECT 60.690 -3.510 68.660 -0.430 ;
        RECT 77.740 -3.510 85.710 -0.430 ;
        RECT 103.580 -3.530 111.550 -0.450 ;
        RECT 124.600 -3.530 132.570 -0.450 ;
        RECT 148.670 -3.560 156.640 -0.480 ;
        RECT 166.740 -3.560 174.710 -0.480 ;
        RECT 89.780 -71.220 97.750 -68.140 ;
        RECT 106.170 -71.220 114.140 -68.140 ;
        RECT 122.130 -71.220 130.100 -68.140 ;
        RECT 139.120 -71.220 147.090 -68.140 ;
      LAYER li1 ;
        RECT 65.960 67.650 149.360 70.840 ;
        RECT 63.090 64.290 150.570 67.650 ;
        RECT 63.150 63.715 72.210 64.290 ;
        RECT 61.555 63.545 73.745 63.715 ;
        RECT 61.555 60.085 61.725 63.545 ;
        RECT 63.150 63.045 72.210 63.545 ;
        RECT 62.630 62.875 72.670 63.045 ;
        RECT 63.150 62.840 72.210 62.875 ;
        RECT 73.575 60.085 73.745 63.545 ;
        RECT 89.850 63.410 91.140 64.290 ;
        RECT 86.890 63.240 94.080 63.410 ;
        RECT 108.080 63.250 109.370 64.290 ;
        RECT 86.890 61.280 87.060 63.240 ;
        RECT 89.850 63.070 91.140 63.240 ;
        RECT 87.965 62.570 93.005 62.740 ;
        RECT 93.910 61.280 94.080 63.240 ;
        RECT 86.890 61.110 94.080 61.280 ;
        RECT 105.120 63.080 112.310 63.250 ;
        RECT 126.480 63.200 127.770 64.290 ;
        RECT 145.250 63.350 146.540 64.290 ;
        RECT 105.120 61.120 105.290 63.080 ;
        RECT 108.080 62.910 109.370 63.080 ;
        RECT 106.195 62.410 111.235 62.580 ;
        RECT 112.140 61.120 112.310 63.080 ;
        RECT 105.120 60.950 112.310 61.120 ;
        RECT 123.520 63.030 130.710 63.200 ;
        RECT 123.520 61.070 123.690 63.030 ;
        RECT 126.480 62.860 127.770 63.030 ;
        RECT 124.595 62.360 129.635 62.530 ;
        RECT 130.540 61.070 130.710 63.030 ;
        RECT 123.520 60.900 130.710 61.070 ;
        RECT 142.290 63.180 149.480 63.350 ;
        RECT 142.290 61.220 142.460 63.180 ;
        RECT 145.250 63.010 146.540 63.180 ;
        RECT 143.365 62.510 148.405 62.680 ;
        RECT 149.310 61.220 149.480 63.180 ;
        RECT 142.290 61.050 149.480 61.220 ;
        RECT 61.555 59.915 73.745 60.085 ;
        RECT 49.090 3.500 51.430 3.530 ;
        RECT 49.020 3.490 64.810 3.500 ;
        RECT 49.020 3.480 179.590 3.490 ;
        RECT 200.470 3.480 206.270 3.500 ;
        RECT 49.020 0.130 206.270 3.480 ;
        RECT 49.020 0.080 65.330 0.130 ;
        RECT 64.040 -0.820 65.330 0.080 ;
        RECT 81.090 -0.820 82.380 0.130 ;
        RECT 61.080 -0.990 68.270 -0.820 ;
        RECT 61.080 -2.950 61.250 -0.990 ;
        RECT 64.040 -1.160 65.330 -0.990 ;
        RECT 62.155 -1.660 67.195 -1.490 ;
        RECT 68.100 -2.950 68.270 -0.990 ;
        RECT 61.080 -3.120 68.270 -2.950 ;
        RECT 78.130 -0.990 85.320 -0.820 ;
        RECT 106.930 -0.840 108.220 0.130 ;
        RECT 127.950 -0.840 129.240 0.130 ;
        RECT 78.130 -2.950 78.300 -0.990 ;
        RECT 81.090 -1.160 82.380 -0.990 ;
        RECT 79.205 -1.660 84.245 -1.490 ;
        RECT 85.150 -2.950 85.320 -0.990 ;
        RECT 78.130 -3.120 85.320 -2.950 ;
        RECT 103.970 -1.010 111.160 -0.840 ;
        RECT 103.970 -2.970 104.140 -1.010 ;
        RECT 106.930 -1.180 108.220 -1.010 ;
        RECT 105.045 -1.680 110.085 -1.510 ;
        RECT 110.990 -2.970 111.160 -1.010 ;
        RECT 103.970 -3.140 111.160 -2.970 ;
        RECT 124.990 -1.010 132.180 -0.840 ;
        RECT 152.020 -0.870 153.310 0.130 ;
        RECT 170.090 -0.870 171.380 0.130 ;
        RECT 171.950 0.120 206.270 0.130 ;
        RECT 200.470 0.110 206.270 0.120 ;
        RECT 124.990 -2.970 125.160 -1.010 ;
        RECT 127.950 -1.180 129.240 -1.010 ;
        RECT 126.065 -1.680 131.105 -1.510 ;
        RECT 132.010 -2.970 132.180 -1.010 ;
        RECT 124.990 -3.140 132.180 -2.970 ;
        RECT 149.060 -1.040 156.250 -0.870 ;
        RECT 149.060 -3.000 149.230 -1.040 ;
        RECT 152.020 -1.210 153.310 -1.040 ;
        RECT 150.135 -1.710 155.175 -1.540 ;
        RECT 156.080 -3.000 156.250 -1.040 ;
        RECT 149.060 -3.170 156.250 -3.000 ;
        RECT 167.130 -1.040 174.320 -0.870 ;
        RECT 167.130 -3.000 167.300 -1.040 ;
        RECT 170.090 -1.210 171.380 -1.040 ;
        RECT 168.205 -1.710 173.245 -1.540 ;
        RECT 174.150 -3.000 174.320 -1.040 ;
        RECT 167.130 -3.170 174.320 -3.000 ;
        RECT 47.750 -64.050 51.710 -64.020 ;
        RECT 91.460 -64.050 145.070 -64.030 ;
        RECT 47.500 -67.530 146.980 -64.050 ;
        RECT 47.500 -67.680 94.530 -67.530 ;
        RECT 93.130 -68.530 94.420 -67.680 ;
        RECT 109.520 -68.530 110.810 -67.530 ;
        RECT 125.480 -68.530 126.770 -67.530 ;
        RECT 142.470 -68.530 143.760 -67.530 ;
        RECT 90.170 -68.700 97.360 -68.530 ;
        RECT 90.170 -70.660 90.340 -68.700 ;
        RECT 93.130 -68.870 94.420 -68.700 ;
        RECT 91.245 -69.370 96.285 -69.200 ;
        RECT 97.190 -70.660 97.360 -68.700 ;
        RECT 90.170 -70.830 97.360 -70.660 ;
        RECT 106.560 -68.700 113.750 -68.530 ;
        RECT 106.560 -70.660 106.730 -68.700 ;
        RECT 109.520 -68.870 110.810 -68.700 ;
        RECT 107.635 -69.370 112.675 -69.200 ;
        RECT 113.580 -70.660 113.750 -68.700 ;
        RECT 106.560 -70.830 113.750 -70.660 ;
        RECT 122.520 -68.700 129.710 -68.530 ;
        RECT 122.520 -70.660 122.690 -68.700 ;
        RECT 125.480 -68.870 126.770 -68.700 ;
        RECT 123.595 -69.370 128.635 -69.200 ;
        RECT 129.540 -70.660 129.710 -68.700 ;
        RECT 122.520 -70.830 129.710 -70.660 ;
        RECT 139.510 -68.700 146.700 -68.530 ;
        RECT 139.510 -70.660 139.680 -68.700 ;
        RECT 142.470 -68.870 143.760 -68.700 ;
        RECT 140.585 -69.370 145.625 -69.200 ;
        RECT 146.530 -70.660 146.700 -68.700 ;
        RECT 139.510 -70.830 146.700 -70.660 ;
      LAYER mcon ;
        RECT 67.220 69.940 68.270 70.440 ;
        RECT 72.470 69.920 73.520 70.420 ;
        RECT 79.530 69.920 80.580 70.420 ;
        RECT 90.280 69.930 91.330 70.430 ;
        RECT 98.530 69.890 99.580 70.390 ;
        RECT 103.890 69.960 104.940 70.460 ;
        RECT 110.340 69.890 111.390 70.390 ;
        RECT 114.630 69.940 115.680 70.440 ;
        RECT 121.400 69.890 122.450 70.390 ;
        RECT 132.230 69.890 133.280 70.390 ;
        RECT 140.890 69.920 141.940 70.420 ;
        RECT 146.700 69.930 147.750 70.430 ;
        RECT 75.740 65.010 76.250 65.570 ;
        RECT 97.570 64.900 98.080 65.460 ;
        RECT 115.590 64.680 116.100 65.240 ;
        RECT 134.690 64.990 135.200 65.550 ;
        RECT 64.860 63.840 65.380 64.240 ;
        RECT 68.450 63.890 68.970 64.290 ;
        RECT 62.710 62.875 72.590 63.045 ;
        RECT 90.190 63.660 90.860 64.300 ;
        RECT 108.420 63.500 109.090 64.140 ;
        RECT 126.820 63.450 127.490 64.090 ;
        RECT 88.045 62.570 92.925 62.740 ;
        RECT 145.590 63.600 146.260 64.240 ;
        RECT 106.275 62.410 111.155 62.580 ;
        RECT 124.675 62.360 129.555 62.530 ;
        RECT 143.445 62.510 148.325 62.680 ;
        RECT 49.500 2.160 49.990 2.680 ;
        RECT 50.400 2.140 50.890 2.660 ;
        RECT 201.870 2.370 202.580 2.970 ;
        RECT 203.050 2.360 203.760 2.960 ;
        RECT 204.030 2.300 204.740 2.900 ;
        RECT 49.460 1.290 49.950 1.810 ;
        RECT 50.390 1.270 50.880 1.790 ;
        RECT 201.850 1.290 202.560 1.890 ;
        RECT 203.030 1.290 203.740 1.890 ;
        RECT 204.040 1.300 204.750 1.900 ;
        RECT 49.430 0.470 49.920 0.990 ;
        RECT 50.400 0.470 50.890 0.990 ;
        RECT 201.850 0.420 202.560 1.020 ;
        RECT 203.040 0.460 203.750 1.060 ;
        RECT 204.030 0.470 204.740 1.070 ;
        RECT 64.380 -0.570 65.050 0.070 ;
        RECT 81.430 -0.570 82.100 0.070 ;
        RECT 107.270 -0.590 107.940 0.050 ;
        RECT 62.235 -1.660 67.115 -1.490 ;
        RECT 128.290 -0.590 128.960 0.050 ;
        RECT 152.360 -0.620 153.030 0.020 ;
        RECT 79.285 -1.660 84.165 -1.490 ;
        RECT 105.125 -1.680 110.005 -1.510 ;
        RECT 170.430 -0.620 171.100 0.020 ;
        RECT 126.145 -1.680 131.025 -1.510 ;
        RECT 150.215 -1.710 155.095 -1.540 ;
        RECT 168.285 -1.710 173.165 -1.540 ;
        RECT 48.210 -65.340 49.040 -64.650 ;
        RECT 49.610 -65.350 50.440 -64.660 ;
        RECT 50.710 -65.360 51.540 -64.670 ;
        RECT 48.210 -66.380 49.040 -65.690 ;
        RECT 49.540 -66.350 50.370 -65.660 ;
        RECT 50.720 -66.270 51.550 -65.580 ;
        RECT 48.190 -67.380 49.020 -66.690 ;
        RECT 49.520 -67.350 50.350 -66.660 ;
        RECT 50.660 -67.340 51.490 -66.650 ;
        RECT 93.470 -68.280 94.140 -67.640 ;
        RECT 109.860 -68.280 110.530 -67.640 ;
        RECT 125.820 -68.280 126.490 -67.640 ;
        RECT 142.810 -68.280 143.480 -67.640 ;
        RECT 91.325 -69.370 96.205 -69.200 ;
        RECT 107.715 -69.370 112.595 -69.200 ;
        RECT 123.675 -69.370 128.555 -69.200 ;
        RECT 140.665 -69.370 145.545 -69.200 ;
      LAYER met1 ;
        RECT 63.340 67.650 150.120 71.430 ;
        RECT 63.090 64.290 150.570 67.650 ;
        RECT 63.150 63.075 72.210 64.290 ;
        RECT 88.190 63.130 92.510 64.290 ;
        RECT 62.650 62.845 72.650 63.075 ;
        RECT 63.150 62.840 72.210 62.845 ;
        RECT 88.330 62.770 92.510 63.130 ;
        RECT 106.420 62.970 110.740 64.290 ;
        RECT 87.985 62.540 92.985 62.770 ;
        RECT 106.560 62.610 110.740 62.970 ;
        RECT 124.820 62.920 129.140 64.290 ;
        RECT 143.590 63.070 147.910 64.290 ;
        RECT 106.215 62.380 111.215 62.610 ;
        RECT 124.960 62.560 129.140 62.920 ;
        RECT 143.730 62.710 147.910 63.070 ;
        RECT 124.615 62.330 129.615 62.560 ;
        RECT 143.385 62.480 148.385 62.710 ;
        RECT 49.090 3.500 51.430 3.530 ;
        RECT 49.020 3.490 64.810 3.500 ;
        RECT 49.020 3.480 179.590 3.490 ;
        RECT 200.470 3.480 206.270 3.500 ;
        RECT 49.020 0.130 206.270 3.480 ;
        RECT 49.020 0.080 66.700 0.130 ;
        RECT 62.380 -1.100 66.700 0.080 ;
        RECT 79.430 -1.100 83.750 0.130 ;
        RECT 62.520 -1.460 66.700 -1.100 ;
        RECT 79.570 -1.460 83.750 -1.100 ;
        RECT 105.270 -1.120 109.590 0.130 ;
        RECT 126.290 -1.120 130.610 0.130 ;
        RECT 62.175 -1.690 67.175 -1.460 ;
        RECT 79.225 -1.690 84.225 -1.460 ;
        RECT 105.410 -1.480 109.590 -1.120 ;
        RECT 126.430 -1.480 130.610 -1.120 ;
        RECT 150.360 -1.150 154.680 0.130 ;
        RECT 168.430 0.120 206.270 0.130 ;
        RECT 168.430 -1.150 172.750 0.120 ;
        RECT 200.470 0.110 206.270 0.120 ;
        RECT 105.065 -1.710 110.065 -1.480 ;
        RECT 126.085 -1.710 131.085 -1.480 ;
        RECT 150.500 -1.510 154.680 -1.150 ;
        RECT 168.570 -1.510 172.750 -1.150 ;
        RECT 150.155 -1.740 155.155 -1.510 ;
        RECT 168.225 -1.740 173.225 -1.510 ;
        RECT 47.750 -64.050 51.710 -64.020 ;
        RECT 91.460 -64.050 145.070 -64.030 ;
        RECT 47.500 -67.530 146.980 -64.050 ;
        RECT 47.500 -67.680 95.790 -67.530 ;
        RECT 91.470 -68.810 95.790 -67.680 ;
        RECT 107.860 -68.810 112.180 -67.530 ;
        RECT 123.820 -68.810 128.140 -67.530 ;
        RECT 140.810 -68.810 145.130 -67.530 ;
        RECT 91.610 -69.170 95.790 -68.810 ;
        RECT 108.000 -69.170 112.180 -68.810 ;
        RECT 123.960 -69.170 128.140 -68.810 ;
        RECT 140.950 -69.170 145.130 -68.810 ;
        RECT 91.265 -69.400 96.265 -69.170 ;
        RECT 107.655 -69.400 112.655 -69.170 ;
        RECT 123.615 -69.400 128.615 -69.170 ;
        RECT 140.605 -69.400 145.605 -69.170 ;
      LAYER via ;
        RECT 67.220 69.940 68.270 70.440 ;
        RECT 72.470 69.920 73.520 70.420 ;
        RECT 79.530 69.920 80.580 70.420 ;
        RECT 90.280 69.930 91.330 70.430 ;
        RECT 98.530 69.890 99.580 70.390 ;
        RECT 103.890 69.960 104.940 70.460 ;
        RECT 110.340 69.890 111.390 70.390 ;
        RECT 114.630 69.940 115.680 70.440 ;
        RECT 121.400 69.890 122.450 70.390 ;
        RECT 132.230 69.890 133.280 70.390 ;
        RECT 140.890 69.920 141.940 70.420 ;
        RECT 146.700 69.930 147.750 70.430 ;
        RECT 49.500 2.160 49.990 2.680 ;
        RECT 50.400 2.140 50.890 2.660 ;
        RECT 201.870 2.370 202.580 2.970 ;
        RECT 203.050 2.360 203.760 2.960 ;
        RECT 204.030 2.300 204.740 2.900 ;
        RECT 49.460 1.290 49.950 1.810 ;
        RECT 50.390 1.270 50.880 1.790 ;
        RECT 201.850 1.290 202.560 1.890 ;
        RECT 203.030 1.290 203.740 1.890 ;
        RECT 204.040 1.300 204.750 1.900 ;
        RECT 49.430 0.470 49.920 0.990 ;
        RECT 50.400 0.470 50.890 0.990 ;
        RECT 201.850 0.420 202.560 1.020 ;
        RECT 203.040 0.460 203.750 1.060 ;
        RECT 204.030 0.470 204.740 1.070 ;
        RECT 48.210 -65.340 49.040 -64.650 ;
        RECT 49.610 -65.350 50.440 -64.660 ;
        RECT 50.710 -65.360 51.540 -64.670 ;
        RECT 48.210 -66.380 49.040 -65.690 ;
        RECT 49.540 -66.350 50.370 -65.660 ;
        RECT 50.720 -66.270 51.550 -65.580 ;
        RECT 48.190 -67.380 49.020 -66.690 ;
        RECT 49.520 -67.350 50.350 -66.660 ;
        RECT 50.660 -67.340 51.490 -66.650 ;
      LAYER met2 ;
        RECT 66.630 69.850 147.850 70.520 ;
        RECT 49.340 0.310 51.310 3.330 ;
        RECT 201.550 0.220 204.900 3.330 ;
        RECT 47.870 -67.530 51.710 -64.130 ;
      LAYER via2 ;
        RECT 67.220 69.940 68.270 70.440 ;
        RECT 72.470 69.920 73.520 70.420 ;
        RECT 79.530 69.920 80.580 70.420 ;
        RECT 90.280 69.930 91.330 70.430 ;
        RECT 98.530 69.890 99.580 70.390 ;
        RECT 103.890 69.960 104.940 70.460 ;
        RECT 110.340 69.890 111.390 70.390 ;
        RECT 114.630 69.940 115.680 70.440 ;
        RECT 121.400 69.890 122.450 70.390 ;
        RECT 132.230 69.890 133.280 70.390 ;
        RECT 140.890 69.920 141.940 70.420 ;
        RECT 146.700 69.930 147.750 70.430 ;
        RECT 49.500 2.160 49.990 2.680 ;
        RECT 50.400 2.140 50.890 2.660 ;
        RECT 49.460 1.290 49.950 1.810 ;
        RECT 50.390 1.270 50.880 1.790 ;
        RECT 49.430 0.470 49.920 0.990 ;
        RECT 50.400 0.470 50.890 0.990 ;
        RECT 201.870 2.370 202.580 2.970 ;
        RECT 203.050 2.360 203.760 2.960 ;
        RECT 204.030 2.300 204.740 2.900 ;
        RECT 201.850 1.290 202.560 1.890 ;
        RECT 203.030 1.290 203.740 1.890 ;
        RECT 204.040 1.300 204.750 1.900 ;
        RECT 201.850 0.420 202.560 1.020 ;
        RECT 203.040 0.460 203.750 1.060 ;
        RECT 204.030 0.470 204.740 1.070 ;
        RECT 48.210 -65.340 49.040 -64.650 ;
        RECT 49.610 -65.350 50.440 -64.660 ;
        RECT 50.710 -65.360 51.540 -64.670 ;
        RECT 48.210 -66.380 49.040 -65.690 ;
        RECT 49.540 -66.350 50.370 -65.660 ;
        RECT 50.720 -66.270 51.550 -65.580 ;
        RECT 48.190 -67.380 49.020 -66.690 ;
        RECT 49.520 -67.350 50.350 -66.660 ;
        RECT 50.660 -67.340 51.490 -66.650 ;
      LAYER met3 ;
        RECT 66.630 69.850 147.850 70.520 ;
        RECT 49.340 0.310 51.310 3.330 ;
        RECT 201.550 0.220 204.900 3.330 ;
        RECT 47.870 -67.530 51.710 -64.130 ;
      LAYER via3 ;
        RECT 67.220 69.940 68.270 70.440 ;
        RECT 72.470 69.920 73.520 70.420 ;
        RECT 79.530 69.920 80.580 70.420 ;
        RECT 90.280 69.930 91.330 70.430 ;
        RECT 98.530 69.890 99.580 70.390 ;
        RECT 103.890 69.960 104.940 70.460 ;
        RECT 110.340 69.890 111.390 70.390 ;
        RECT 114.630 69.940 115.680 70.440 ;
        RECT 121.400 69.890 122.450 70.390 ;
        RECT 132.230 69.890 133.280 70.390 ;
        RECT 140.890 69.920 141.940 70.420 ;
        RECT 146.700 69.930 147.750 70.430 ;
        RECT 49.500 2.160 49.990 2.680 ;
        RECT 50.400 2.140 50.890 2.660 ;
        RECT 49.460 1.290 49.950 1.810 ;
        RECT 50.390 1.270 50.880 1.790 ;
        RECT 49.430 0.470 49.920 0.990 ;
        RECT 50.400 0.470 50.890 0.990 ;
        RECT 201.870 2.370 202.580 2.970 ;
        RECT 203.050 2.360 203.760 2.960 ;
        RECT 204.030 2.300 204.740 2.900 ;
        RECT 201.850 1.290 202.560 1.890 ;
        RECT 203.030 1.290 203.740 1.890 ;
        RECT 204.040 1.300 204.750 1.900 ;
        RECT 201.850 0.420 202.560 1.020 ;
        RECT 203.040 0.460 203.750 1.060 ;
        RECT 204.030 0.470 204.740 1.070 ;
        RECT 48.210 -65.340 49.040 -64.650 ;
        RECT 49.610 -65.350 50.440 -64.660 ;
        RECT 50.710 -65.360 51.540 -64.670 ;
        RECT 48.210 -66.380 49.040 -65.690 ;
        RECT 49.540 -66.350 50.370 -65.660 ;
        RECT 50.720 -66.270 51.550 -65.580 ;
        RECT 48.190 -67.380 49.020 -66.690 ;
        RECT 49.520 -67.350 50.350 -66.660 ;
        RECT 50.660 -67.340 51.490 -66.650 ;
      LAYER met4 ;
        RECT 46.210 69.710 207.460 73.770 ;
        RECT 46.210 -125.470 51.900 69.710 ;
        RECT 201.240 -125.470 207.460 69.710 ;
        RECT 46.210 -130.890 207.460 -125.470 ;
    END
  END VDD
  PIN VSS
    USE GROUND ;
    ANTENNADIFFAREA 33.846699 ;
    PORT
      LAYER pwell ;
        RECT 63.900 49.400 71.290 57.880 ;
      LAYER li1 ;
        RECT 64.080 57.530 71.110 57.700 ;
        RECT 64.080 49.750 64.250 57.530 ;
        RECT 64.730 52.330 70.460 52.390 ;
        RECT 64.720 49.750 70.470 52.330 ;
        RECT 70.940 49.750 71.110 57.530 ;
        RECT 64.080 49.580 71.110 49.750 ;
        RECT 44.170 47.360 57.170 47.380 ;
        RECT 64.720 47.360 70.470 49.580 ;
        RECT 44.170 47.270 70.470 47.360 ;
        RECT 40.870 43.880 70.470 47.270 ;
        RECT 40.870 43.850 57.170 43.880 ;
        RECT 64.720 43.860 70.470 43.880 ;
        RECT 40.870 43.740 52.530 43.850 ;
        RECT 42.840 11.200 158.240 11.220 ;
        RECT 40.330 7.900 158.240 11.200 ;
        RECT 40.330 7.880 52.250 7.900 ;
        RECT 42.840 7.870 52.250 7.880 ;
        RECT 43.730 -53.150 175.930 -53.140 ;
        RECT 40.230 -56.460 175.930 -53.150 ;
        RECT 40.230 -56.470 56.210 -56.460 ;
        RECT 40.230 -56.480 52.880 -56.470 ;
        RECT 89.030 -124.240 148.140 -121.220 ;
        RECT 89.300 -135.230 147.730 -124.240 ;
      LAYER mcon ;
        RECT 64.810 50.320 70.380 52.305 ;
        RECT 41.320 45.980 41.970 46.550 ;
        RECT 42.280 45.990 42.930 46.560 ;
        RECT 43.130 45.960 43.780 46.530 ;
        RECT 41.300 44.970 41.950 45.540 ;
        RECT 42.240 44.980 42.890 45.550 ;
        RECT 43.140 45.000 43.790 45.570 ;
        RECT 41.290 44.090 41.940 44.660 ;
        RECT 42.260 44.100 42.910 44.670 ;
        RECT 43.140 44.120 43.790 44.690 ;
        RECT 40.780 10.140 41.370 10.670 ;
        RECT 41.560 10.120 42.150 10.650 ;
        RECT 42.420 10.060 43.010 10.590 ;
        RECT 40.730 9.060 41.320 9.590 ;
        RECT 41.550 9.070 42.140 9.600 ;
        RECT 42.420 9.130 43.010 9.660 ;
        RECT 92.680 8.910 93.790 9.910 ;
        RECT 110.910 8.750 112.020 9.750 ;
        RECT 129.310 8.700 130.420 9.700 ;
        RECT 148.080 8.850 149.190 9.850 ;
        RECT 40.700 8.150 41.290 8.680 ;
        RECT 41.520 8.140 42.110 8.670 ;
        RECT 42.380 8.150 42.970 8.680 ;
        RECT 40.610 -54.310 41.370 -53.730 ;
        RECT 41.680 -54.290 42.440 -53.710 ;
        RECT 42.770 -54.280 43.530 -53.700 ;
        RECT 40.590 -55.190 41.350 -54.610 ;
        RECT 41.690 -55.190 42.450 -54.610 ;
        RECT 42.740 -55.180 43.500 -54.600 ;
        RECT 66.870 -55.320 67.980 -54.320 ;
        RECT 83.920 -55.320 85.030 -54.320 ;
        RECT 109.760 -55.340 110.870 -54.340 ;
        RECT 130.780 -55.340 131.890 -54.340 ;
        RECT 154.850 -55.370 155.960 -54.370 ;
        RECT 172.920 -55.370 174.030 -54.370 ;
        RECT 40.600 -56.100 41.360 -55.520 ;
        RECT 41.670 -56.100 42.430 -55.520 ;
        RECT 42.730 -56.100 43.490 -55.520 ;
        RECT 95.960 -123.030 97.070 -122.030 ;
        RECT 112.350 -123.030 113.460 -122.030 ;
        RECT 128.310 -123.030 129.420 -122.030 ;
        RECT 145.300 -123.030 146.410 -122.030 ;
        RECT 90.360 -134.550 92.260 -133.780 ;
        RECT 101.240 -134.470 103.140 -133.700 ;
        RECT 120.150 -134.550 122.050 -133.780 ;
        RECT 133.060 -134.470 134.960 -133.700 ;
        RECT 144.840 -134.470 146.740 -133.700 ;
      LAYER met1 ;
        RECT 64.750 52.330 70.440 52.335 ;
        RECT 44.170 47.360 57.170 47.380 ;
        RECT 64.720 47.360 70.470 52.330 ;
        RECT 44.170 47.270 70.470 47.360 ;
        RECT 40.870 43.880 70.470 47.270 ;
        RECT 40.870 43.850 57.170 43.880 ;
        RECT 64.720 43.860 70.470 43.880 ;
        RECT 40.870 43.740 52.530 43.850 ;
        RECT 42.840 11.200 158.240 11.220 ;
        RECT 40.330 7.900 158.240 11.200 ;
        RECT 40.330 7.880 52.250 7.900 ;
        RECT 42.840 7.870 52.250 7.880 ;
        RECT 43.730 -53.150 175.930 -53.140 ;
        RECT 40.230 -56.460 175.930 -53.150 ;
        RECT 40.230 -56.470 56.210 -56.460 ;
        RECT 40.230 -56.480 52.880 -56.470 ;
        RECT 89.030 -121.240 148.140 -121.220 ;
        RECT 87.680 -124.240 148.140 -121.240 ;
        RECT 87.680 -135.220 147.730 -124.240 ;
        RECT 89.300 -135.230 147.730 -135.220 ;
      LAYER via ;
        RECT 41.320 45.980 41.970 46.550 ;
        RECT 42.280 45.990 42.930 46.560 ;
        RECT 43.130 45.960 43.780 46.530 ;
        RECT 41.300 44.970 41.950 45.540 ;
        RECT 42.240 44.980 42.890 45.550 ;
        RECT 43.140 45.000 43.790 45.570 ;
        RECT 41.290 44.090 41.940 44.660 ;
        RECT 42.260 44.100 42.910 44.670 ;
        RECT 43.140 44.120 43.790 44.690 ;
        RECT 40.780 10.140 41.370 10.670 ;
        RECT 41.560 10.120 42.150 10.650 ;
        RECT 42.420 10.060 43.010 10.590 ;
        RECT 40.730 9.060 41.320 9.590 ;
        RECT 41.550 9.070 42.140 9.600 ;
        RECT 42.420 9.130 43.010 9.660 ;
        RECT 40.700 8.150 41.290 8.680 ;
        RECT 41.520 8.140 42.110 8.670 ;
        RECT 42.380 8.150 42.970 8.680 ;
        RECT 40.610 -54.310 41.370 -53.730 ;
        RECT 41.680 -54.290 42.440 -53.710 ;
        RECT 42.770 -54.280 43.530 -53.700 ;
        RECT 40.590 -55.190 41.350 -54.610 ;
        RECT 41.690 -55.190 42.450 -54.610 ;
        RECT 42.740 -55.180 43.500 -54.600 ;
        RECT 40.600 -56.100 41.360 -55.520 ;
        RECT 41.670 -56.100 42.430 -55.520 ;
        RECT 42.730 -56.100 43.490 -55.520 ;
        RECT 90.360 -134.550 92.260 -133.780 ;
        RECT 101.240 -134.470 103.140 -133.700 ;
        RECT 120.150 -134.550 122.050 -133.780 ;
        RECT 133.060 -134.470 134.960 -133.700 ;
        RECT 144.840 -134.470 146.740 -133.700 ;
      LAYER met2 ;
        RECT 41.120 43.900 44.060 46.990 ;
        RECT 40.480 7.950 43.380 11.080 ;
        RECT 40.440 -56.260 43.650 -53.360 ;
        RECT 89.780 -134.840 147.210 -133.150 ;
      LAYER via2 ;
        RECT 41.320 45.980 41.970 46.550 ;
        RECT 42.280 45.990 42.930 46.560 ;
        RECT 43.130 45.960 43.780 46.530 ;
        RECT 41.300 44.970 41.950 45.540 ;
        RECT 42.240 44.980 42.890 45.550 ;
        RECT 43.140 45.000 43.790 45.570 ;
        RECT 41.290 44.090 41.940 44.660 ;
        RECT 42.260 44.100 42.910 44.670 ;
        RECT 43.140 44.120 43.790 44.690 ;
        RECT 40.780 10.140 41.370 10.670 ;
        RECT 41.560 10.120 42.150 10.650 ;
        RECT 42.420 10.060 43.010 10.590 ;
        RECT 40.730 9.060 41.320 9.590 ;
        RECT 41.550 9.070 42.140 9.600 ;
        RECT 42.420 9.130 43.010 9.660 ;
        RECT 40.700 8.150 41.290 8.680 ;
        RECT 41.520 8.140 42.110 8.670 ;
        RECT 42.380 8.150 42.970 8.680 ;
        RECT 40.610 -54.310 41.370 -53.730 ;
        RECT 41.680 -54.290 42.440 -53.710 ;
        RECT 42.770 -54.280 43.530 -53.700 ;
        RECT 40.590 -55.190 41.350 -54.610 ;
        RECT 41.690 -55.190 42.450 -54.610 ;
        RECT 42.740 -55.180 43.500 -54.600 ;
        RECT 40.600 -56.100 41.360 -55.520 ;
        RECT 41.670 -56.100 42.430 -55.520 ;
        RECT 42.730 -56.100 43.490 -55.520 ;
        RECT 90.360 -134.550 92.260 -133.780 ;
        RECT 101.240 -134.470 103.140 -133.700 ;
        RECT 120.150 -134.550 122.050 -133.780 ;
        RECT 133.060 -134.470 134.960 -133.700 ;
        RECT 144.840 -134.470 146.740 -133.700 ;
      LAYER met3 ;
        RECT 41.120 43.900 44.060 46.990 ;
        RECT 40.480 7.950 43.380 11.080 ;
        RECT 40.440 -56.260 43.650 -53.360 ;
        RECT 89.780 -134.840 147.210 -133.150 ;
      LAYER via3 ;
        RECT 41.320 45.980 41.970 46.550 ;
        RECT 42.280 45.990 42.930 46.560 ;
        RECT 43.130 45.960 43.780 46.530 ;
        RECT 41.300 44.970 41.950 45.540 ;
        RECT 42.240 44.980 42.890 45.550 ;
        RECT 43.140 45.000 43.790 45.570 ;
        RECT 41.290 44.090 41.940 44.660 ;
        RECT 42.260 44.100 42.910 44.670 ;
        RECT 43.140 44.120 43.790 44.690 ;
        RECT 40.780 10.140 41.370 10.670 ;
        RECT 41.560 10.120 42.150 10.650 ;
        RECT 42.420 10.060 43.010 10.590 ;
        RECT 40.730 9.060 41.320 9.590 ;
        RECT 41.550 9.070 42.140 9.600 ;
        RECT 42.420 9.130 43.010 9.660 ;
        RECT 40.700 8.150 41.290 8.680 ;
        RECT 41.520 8.140 42.110 8.670 ;
        RECT 42.380 8.150 42.970 8.680 ;
        RECT 40.610 -54.310 41.370 -53.730 ;
        RECT 41.680 -54.290 42.440 -53.710 ;
        RECT 42.770 -54.280 43.530 -53.700 ;
        RECT 40.590 -55.190 41.350 -54.610 ;
        RECT 41.690 -55.190 42.450 -54.610 ;
        RECT 42.740 -55.180 43.500 -54.600 ;
        RECT 40.600 -56.100 41.360 -55.520 ;
        RECT 41.670 -56.100 42.430 -55.520 ;
        RECT 42.730 -56.100 43.490 -55.520 ;
        RECT 90.360 -134.550 92.260 -133.780 ;
        RECT 101.240 -134.470 103.140 -133.700 ;
        RECT 120.150 -134.550 122.050 -133.780 ;
        RECT 133.060 -134.470 134.960 -133.700 ;
        RECT 144.840 -134.470 146.740 -133.700 ;
      LAYER met4 ;
        RECT 38.770 75.200 214.730 78.340 ;
        RECT 38.770 -132.380 44.620 75.200 ;
        RECT 208.880 -132.380 214.730 75.200 ;
        RECT 38.770 -137.180 214.730 -132.380 ;
    END
  END VSS
  OBS
      LAYER pwell ;
        RECT 36.730 -137.180 220.190 78.520 ;
        RECT 85.340 16.310 95.230 58.890 ;
        RECT 103.570 16.150 113.460 58.730 ;
        RECT 121.970 16.100 131.860 58.680 ;
        RECT 140.740 16.250 150.630 58.830 ;
        RECT 59.530 -47.920 69.420 -5.340 ;
        RECT 76.580 -47.920 86.470 -5.340 ;
        RECT 102.420 -47.940 112.310 -5.360 ;
        RECT 123.440 -47.940 133.330 -5.360 ;
        RECT 147.510 -47.970 157.400 -5.390 ;
        RECT 165.580 -47.970 175.470 -5.390 ;
        RECT 88.620 -115.630 98.510 -73.050 ;
        RECT 105.010 -115.630 114.900 -73.050 ;
        RECT 120.970 -115.630 130.860 -73.050 ;
        RECT 137.960 -115.630 147.850 -73.050 ;
      LAYER li1 ;
        RECT 36.730 -137.180 220.190 78.520 ;
        RECT 62.245 60.815 62.415 62.815 ;
        RECT 72.885 60.815 73.055 62.815 ;
        RECT 87.580 62.010 87.750 62.510 ;
        RECT 93.220 62.010 93.390 62.510 ;
        RECT 87.965 61.780 93.005 61.950 ;
        RECT 105.810 61.850 105.980 62.350 ;
        RECT 111.450 61.850 111.620 62.350 ;
        RECT 124.210 61.800 124.380 62.300 ;
        RECT 129.850 61.800 130.020 62.300 ;
        RECT 142.980 61.950 143.150 62.450 ;
        RECT 148.620 61.950 148.790 62.450 ;
        RECT 106.195 61.620 111.235 61.790 ;
        RECT 124.595 61.570 129.635 61.740 ;
        RECT 143.365 61.720 148.405 61.890 ;
        RECT 62.630 60.585 72.670 60.755 ;
        RECT 85.580 58.480 94.990 58.650 ;
        RECT 64.730 54.890 70.460 57.050 ;
        RECT 85.580 16.720 85.750 58.480 ;
        RECT 87.040 17.580 87.210 57.620 ;
        RECT 88.620 17.580 88.790 57.620 ;
        RECT 90.200 17.580 90.370 57.620 ;
        RECT 91.780 17.580 91.950 57.620 ;
        RECT 93.360 17.580 93.530 57.620 ;
        RECT 94.820 16.720 94.990 58.480 ;
        RECT 85.580 16.550 94.990 16.720 ;
        RECT 103.810 58.320 113.220 58.490 ;
        RECT 103.810 16.560 103.980 58.320 ;
        RECT 105.270 17.420 105.440 57.460 ;
        RECT 106.850 17.420 107.020 57.460 ;
        RECT 108.430 17.420 108.600 57.460 ;
        RECT 110.010 17.420 110.180 57.460 ;
        RECT 111.590 17.420 111.760 57.460 ;
        RECT 113.050 16.560 113.220 58.320 ;
        RECT 103.810 16.390 113.220 16.560 ;
        RECT 122.210 58.270 131.620 58.440 ;
        RECT 122.210 16.510 122.380 58.270 ;
        RECT 123.670 17.370 123.840 57.410 ;
        RECT 125.250 17.370 125.420 57.410 ;
        RECT 126.830 17.370 127.000 57.410 ;
        RECT 128.410 17.370 128.580 57.410 ;
        RECT 129.990 17.370 130.160 57.410 ;
        RECT 131.450 16.510 131.620 58.270 ;
        RECT 122.210 16.340 131.620 16.510 ;
        RECT 140.980 58.420 150.390 58.590 ;
        RECT 140.980 16.660 141.150 58.420 ;
        RECT 142.440 17.520 142.610 57.560 ;
        RECT 144.020 17.520 144.190 57.560 ;
        RECT 145.600 17.520 145.770 57.560 ;
        RECT 147.180 17.520 147.350 57.560 ;
        RECT 148.760 17.520 148.930 57.560 ;
        RECT 150.220 16.660 150.390 58.420 ;
        RECT 140.980 16.490 150.390 16.660 ;
        RECT 178.060 6.990 182.050 31.190 ;
        RECT 61.770 -2.220 61.940 -1.720 ;
        RECT 67.410 -2.220 67.580 -1.720 ;
        RECT 78.820 -2.220 78.990 -1.720 ;
        RECT 84.460 -2.220 84.630 -1.720 ;
        RECT 104.660 -2.240 104.830 -1.740 ;
        RECT 110.300 -2.240 110.470 -1.740 ;
        RECT 125.680 -2.240 125.850 -1.740 ;
        RECT 131.320 -2.240 131.490 -1.740 ;
        RECT 149.750 -2.270 149.920 -1.770 ;
        RECT 155.390 -2.270 155.560 -1.770 ;
        RECT 167.820 -2.270 167.990 -1.770 ;
        RECT 173.460 -2.270 173.630 -1.770 ;
        RECT 62.155 -2.450 67.195 -2.280 ;
        RECT 79.205 -2.450 84.245 -2.280 ;
        RECT 105.045 -2.470 110.085 -2.300 ;
        RECT 126.065 -2.470 131.105 -2.300 ;
        RECT 150.135 -2.500 155.175 -2.330 ;
        RECT 168.205 -2.500 173.245 -2.330 ;
        RECT 59.770 -5.750 69.180 -5.580 ;
        RECT 59.770 -47.510 59.940 -5.750 ;
        RECT 61.230 -46.650 61.400 -6.610 ;
        RECT 62.810 -46.650 62.980 -6.610 ;
        RECT 64.390 -46.650 64.560 -6.610 ;
        RECT 65.970 -46.650 66.140 -6.610 ;
        RECT 67.550 -46.650 67.720 -6.610 ;
        RECT 69.010 -47.510 69.180 -5.750 ;
        RECT 59.770 -47.680 69.180 -47.510 ;
        RECT 76.820 -5.750 86.230 -5.580 ;
        RECT 76.820 -47.510 76.990 -5.750 ;
        RECT 78.280 -46.650 78.450 -6.610 ;
        RECT 79.860 -46.650 80.030 -6.610 ;
        RECT 81.440 -46.650 81.610 -6.610 ;
        RECT 83.020 -46.650 83.190 -6.610 ;
        RECT 84.600 -46.650 84.770 -6.610 ;
        RECT 86.060 -47.510 86.230 -5.750 ;
        RECT 76.820 -47.680 86.230 -47.510 ;
        RECT 102.660 -5.770 112.070 -5.600 ;
        RECT 102.660 -47.530 102.830 -5.770 ;
        RECT 104.120 -46.670 104.290 -6.630 ;
        RECT 105.700 -46.670 105.870 -6.630 ;
        RECT 107.280 -46.670 107.450 -6.630 ;
        RECT 108.860 -46.670 109.030 -6.630 ;
        RECT 110.440 -46.670 110.610 -6.630 ;
        RECT 111.900 -47.530 112.070 -5.770 ;
        RECT 102.660 -47.700 112.070 -47.530 ;
        RECT 123.680 -5.770 133.090 -5.600 ;
        RECT 123.680 -47.530 123.850 -5.770 ;
        RECT 125.140 -46.670 125.310 -6.630 ;
        RECT 126.720 -46.670 126.890 -6.630 ;
        RECT 128.300 -46.670 128.470 -6.630 ;
        RECT 129.880 -46.670 130.050 -6.630 ;
        RECT 131.460 -46.670 131.630 -6.630 ;
        RECT 132.920 -47.530 133.090 -5.770 ;
        RECT 123.680 -47.700 133.090 -47.530 ;
        RECT 147.750 -5.800 157.160 -5.630 ;
        RECT 147.750 -47.560 147.920 -5.800 ;
        RECT 149.210 -46.700 149.380 -6.660 ;
        RECT 150.790 -46.700 150.960 -6.660 ;
        RECT 152.370 -46.700 152.540 -6.660 ;
        RECT 153.950 -46.700 154.120 -6.660 ;
        RECT 155.530 -46.700 155.700 -6.660 ;
        RECT 156.990 -47.560 157.160 -5.800 ;
        RECT 147.750 -47.730 157.160 -47.560 ;
        RECT 165.820 -5.800 175.230 -5.630 ;
        RECT 165.820 -47.560 165.990 -5.800 ;
        RECT 167.280 -46.700 167.450 -6.660 ;
        RECT 168.860 -46.700 169.030 -6.660 ;
        RECT 170.440 -46.700 170.610 -6.660 ;
        RECT 172.020 -46.700 172.190 -6.660 ;
        RECT 173.600 -46.700 173.770 -6.660 ;
        RECT 175.060 -47.560 175.230 -5.800 ;
        RECT 165.820 -47.730 175.230 -47.560 ;
        RECT 178.070 -57.480 182.020 -43.300 ;
        RECT 90.860 -69.930 91.030 -69.430 ;
        RECT 96.500 -69.930 96.670 -69.430 ;
        RECT 107.250 -69.930 107.420 -69.430 ;
        RECT 112.890 -69.930 113.060 -69.430 ;
        RECT 123.210 -69.930 123.380 -69.430 ;
        RECT 128.850 -69.930 129.020 -69.430 ;
        RECT 140.200 -69.930 140.370 -69.430 ;
        RECT 145.840 -69.930 146.010 -69.430 ;
        RECT 91.245 -70.160 96.285 -69.990 ;
        RECT 107.635 -70.160 112.675 -69.990 ;
        RECT 123.595 -70.160 128.635 -69.990 ;
        RECT 140.585 -70.160 145.625 -69.990 ;
        RECT 88.860 -73.460 98.270 -73.290 ;
        RECT 88.860 -115.220 89.030 -73.460 ;
        RECT 90.320 -114.360 90.490 -74.320 ;
        RECT 91.900 -114.360 92.070 -74.320 ;
        RECT 93.480 -114.360 93.650 -74.320 ;
        RECT 95.060 -114.360 95.230 -74.320 ;
        RECT 96.640 -114.360 96.810 -74.320 ;
        RECT 98.100 -115.220 98.270 -73.460 ;
        RECT 88.860 -115.390 98.270 -115.220 ;
        RECT 105.250 -73.460 114.660 -73.290 ;
        RECT 105.250 -115.220 105.420 -73.460 ;
        RECT 106.710 -114.360 106.880 -74.320 ;
        RECT 108.290 -114.360 108.460 -74.320 ;
        RECT 109.870 -114.360 110.040 -74.320 ;
        RECT 111.450 -114.360 111.620 -74.320 ;
        RECT 113.030 -114.360 113.200 -74.320 ;
        RECT 114.490 -115.220 114.660 -73.460 ;
        RECT 105.250 -115.390 114.660 -115.220 ;
        RECT 121.210 -73.460 130.620 -73.290 ;
        RECT 121.210 -115.220 121.380 -73.460 ;
        RECT 122.670 -114.360 122.840 -74.320 ;
        RECT 124.250 -114.360 124.420 -74.320 ;
        RECT 125.830 -114.360 126.000 -74.320 ;
        RECT 127.410 -114.360 127.580 -74.320 ;
        RECT 128.990 -114.360 129.160 -74.320 ;
        RECT 130.450 -115.220 130.620 -73.460 ;
        RECT 121.210 -115.390 130.620 -115.220 ;
        RECT 138.200 -73.460 147.610 -73.290 ;
        RECT 138.200 -115.220 138.370 -73.460 ;
        RECT 139.660 -114.360 139.830 -74.320 ;
        RECT 141.240 -114.360 141.410 -74.320 ;
        RECT 142.820 -114.360 142.990 -74.320 ;
        RECT 144.400 -114.360 144.570 -74.320 ;
        RECT 145.980 -114.360 146.150 -74.320 ;
        RECT 147.440 -115.220 147.610 -73.460 ;
        RECT 138.200 -115.390 147.610 -115.220 ;
      LAYER mcon ;
        RECT 36.730 -137.180 220.190 78.520 ;
        RECT 62.245 60.895 62.415 62.735 ;
        RECT 72.885 60.895 73.055 62.735 ;
        RECT 87.580 62.090 87.750 62.430 ;
        RECT 93.220 62.090 93.390 62.430 ;
        RECT 88.045 61.780 92.925 61.950 ;
        RECT 105.810 61.930 105.980 62.270 ;
        RECT 111.450 61.930 111.620 62.270 ;
        RECT 124.210 61.880 124.380 62.220 ;
        RECT 129.850 61.880 130.020 62.220 ;
        RECT 142.980 62.030 143.150 62.370 ;
        RECT 148.620 62.030 148.790 62.370 ;
        RECT 106.275 61.620 111.155 61.790 ;
        RECT 124.675 61.570 129.555 61.740 ;
        RECT 143.445 61.720 148.325 61.890 ;
        RECT 62.710 60.585 72.590 60.755 ;
        RECT 64.810 54.975 70.380 56.960 ;
        RECT 87.040 17.660 87.210 57.540 ;
        RECT 88.620 17.660 88.790 57.540 ;
        RECT 90.200 17.660 90.370 57.540 ;
        RECT 91.780 17.660 91.950 57.540 ;
        RECT 93.360 17.660 93.530 57.540 ;
        RECT 105.270 17.500 105.440 57.380 ;
        RECT 106.850 17.500 107.020 57.380 ;
        RECT 108.430 17.500 108.600 57.380 ;
        RECT 110.010 17.500 110.180 57.380 ;
        RECT 111.590 17.500 111.760 57.380 ;
        RECT 123.670 17.450 123.840 57.330 ;
        RECT 125.250 17.450 125.420 57.330 ;
        RECT 126.830 17.450 127.000 57.330 ;
        RECT 128.410 17.450 128.580 57.330 ;
        RECT 129.990 17.450 130.160 57.330 ;
        RECT 142.440 17.600 142.610 57.480 ;
        RECT 144.020 17.600 144.190 57.480 ;
        RECT 145.600 17.600 145.770 57.480 ;
        RECT 147.180 17.600 147.350 57.480 ;
        RECT 148.760 17.600 148.930 57.480 ;
        RECT 178.250 29.440 179.870 30.110 ;
        RECT 180.290 29.390 181.910 30.060 ;
        RECT 178.230 28.400 179.850 29.070 ;
        RECT 180.270 28.440 181.890 29.110 ;
        RECT 178.230 27.530 179.850 28.200 ;
        RECT 180.260 27.530 181.880 28.200 ;
        RECT 178.220 26.610 179.840 27.280 ;
        RECT 180.260 26.630 181.880 27.300 ;
        RECT 178.280 17.820 179.330 18.570 ;
        RECT 180.530 17.870 181.580 18.620 ;
        RECT 178.210 9.810 179.830 10.480 ;
        RECT 180.310 9.830 181.930 10.500 ;
        RECT 178.200 8.940 179.820 9.610 ;
        RECT 180.340 8.940 181.960 9.610 ;
        RECT 178.210 8.010 179.830 8.680 ;
        RECT 180.350 8.020 181.970 8.690 ;
        RECT 61.770 -2.140 61.940 -1.800 ;
        RECT 67.410 -2.140 67.580 -1.800 ;
        RECT 78.820 -2.140 78.990 -1.800 ;
        RECT 84.460 -2.140 84.630 -1.800 ;
        RECT 104.660 -2.160 104.830 -1.820 ;
        RECT 110.300 -2.160 110.470 -1.820 ;
        RECT 125.680 -2.160 125.850 -1.820 ;
        RECT 131.320 -2.160 131.490 -1.820 ;
        RECT 149.750 -2.190 149.920 -1.850 ;
        RECT 155.390 -2.190 155.560 -1.850 ;
        RECT 167.820 -2.190 167.990 -1.850 ;
        RECT 173.460 -2.190 173.630 -1.850 ;
        RECT 62.235 -2.450 67.115 -2.280 ;
        RECT 79.285 -2.450 84.165 -2.280 ;
        RECT 105.125 -2.470 110.005 -2.300 ;
        RECT 126.145 -2.470 131.025 -2.300 ;
        RECT 150.215 -2.500 155.095 -2.330 ;
        RECT 168.285 -2.500 173.165 -2.330 ;
        RECT 61.230 -46.570 61.400 -6.690 ;
        RECT 62.810 -46.570 62.980 -6.690 ;
        RECT 64.390 -46.570 64.560 -6.690 ;
        RECT 65.970 -46.570 66.140 -6.690 ;
        RECT 67.550 -46.570 67.720 -6.690 ;
        RECT 78.280 -46.570 78.450 -6.690 ;
        RECT 79.860 -46.570 80.030 -6.690 ;
        RECT 81.440 -46.570 81.610 -6.690 ;
        RECT 83.020 -46.570 83.190 -6.690 ;
        RECT 84.600 -46.570 84.770 -6.690 ;
        RECT 104.120 -46.590 104.290 -6.710 ;
        RECT 105.700 -46.590 105.870 -6.710 ;
        RECT 107.280 -46.590 107.450 -6.710 ;
        RECT 108.860 -46.590 109.030 -6.710 ;
        RECT 110.440 -46.590 110.610 -6.710 ;
        RECT 125.140 -46.590 125.310 -6.710 ;
        RECT 126.720 -46.590 126.890 -6.710 ;
        RECT 128.300 -46.590 128.470 -6.710 ;
        RECT 129.880 -46.590 130.050 -6.710 ;
        RECT 131.460 -46.590 131.630 -6.710 ;
        RECT 149.210 -46.620 149.380 -6.740 ;
        RECT 150.790 -46.620 150.960 -6.740 ;
        RECT 152.370 -46.620 152.540 -6.740 ;
        RECT 153.950 -46.620 154.120 -6.740 ;
        RECT 155.530 -46.620 155.700 -6.740 ;
        RECT 167.280 -46.620 167.450 -6.740 ;
        RECT 168.860 -46.620 169.030 -6.740 ;
        RECT 170.440 -46.620 170.610 -6.740 ;
        RECT 172.020 -46.620 172.190 -6.740 ;
        RECT 173.600 -46.620 173.770 -6.740 ;
        RECT 178.560 -44.520 179.450 -43.780 ;
        RECT 180.460 -44.540 181.350 -43.800 ;
        RECT 178.520 -46.010 179.410 -45.270 ;
        RECT 180.450 -46.000 181.340 -45.260 ;
        RECT 178.470 -54.760 179.360 -54.020 ;
        RECT 180.670 -54.720 181.560 -53.980 ;
        RECT 178.420 -57.190 179.310 -56.450 ;
        RECT 180.670 -57.170 181.560 -56.430 ;
        RECT 90.860 -69.850 91.030 -69.510 ;
        RECT 96.500 -69.850 96.670 -69.510 ;
        RECT 107.250 -69.850 107.420 -69.510 ;
        RECT 112.890 -69.850 113.060 -69.510 ;
        RECT 123.210 -69.850 123.380 -69.510 ;
        RECT 128.850 -69.850 129.020 -69.510 ;
        RECT 140.200 -69.850 140.370 -69.510 ;
        RECT 145.840 -69.850 146.010 -69.510 ;
        RECT 91.325 -70.160 96.205 -69.990 ;
        RECT 107.715 -70.160 112.595 -69.990 ;
        RECT 123.675 -70.160 128.555 -69.990 ;
        RECT 140.665 -70.160 145.545 -69.990 ;
        RECT 90.320 -114.280 90.490 -74.400 ;
        RECT 91.900 -114.280 92.070 -74.400 ;
        RECT 93.480 -114.280 93.650 -74.400 ;
        RECT 95.060 -114.280 95.230 -74.400 ;
        RECT 96.640 -114.280 96.810 -74.400 ;
        RECT 106.710 -114.280 106.880 -74.400 ;
        RECT 108.290 -114.280 108.460 -74.400 ;
        RECT 109.870 -114.280 110.040 -74.400 ;
        RECT 111.450 -114.280 111.620 -74.400 ;
        RECT 113.030 -114.280 113.200 -74.400 ;
        RECT 122.670 -114.280 122.840 -74.400 ;
        RECT 124.250 -114.280 124.420 -74.400 ;
        RECT 125.830 -114.280 126.000 -74.400 ;
        RECT 127.410 -114.280 127.580 -74.400 ;
        RECT 128.990 -114.280 129.160 -74.400 ;
        RECT 139.660 -114.280 139.830 -74.400 ;
        RECT 141.240 -114.280 141.410 -74.400 ;
        RECT 142.820 -114.280 142.990 -74.400 ;
        RECT 144.400 -114.280 144.570 -74.400 ;
        RECT 145.980 -114.280 146.150 -74.400 ;
      LAYER met1 ;
        RECT 82.560 62.820 86.190 62.900 ;
        RECT 77.710 62.810 86.190 62.820 ;
        RECT 62.215 62.180 62.445 62.795 ;
        RECT 72.810 62.490 86.190 62.810 ;
        RECT 72.810 62.180 87.790 62.490 ;
        RECT 62.215 62.030 87.790 62.180 ;
        RECT 93.190 62.030 93.420 62.490 ;
        RECT 100.790 62.330 104.420 62.740 ;
        RECT 62.215 61.580 86.190 62.030 ;
        RECT 88.190 61.980 92.680 62.010 ;
        RECT 87.985 61.750 92.985 61.980 ;
        RECT 100.790 61.870 106.020 62.330 ;
        RECT 111.420 61.870 111.650 62.330 ;
        RECT 119.190 62.280 122.820 62.690 ;
        RECT 137.960 62.430 141.590 62.840 ;
        RECT 62.215 61.490 84.150 61.580 ;
        RECT 62.215 60.835 62.445 61.490 ;
        RECT 72.810 60.820 84.150 61.490 ;
        RECT 75.050 60.810 84.150 60.820 ;
        RECT 63.080 60.785 72.100 60.790 ;
        RECT 62.650 60.555 72.650 60.785 ;
        RECT 63.080 60.350 72.100 60.555 ;
        RECT 64.730 59.860 72.100 60.350 ;
        RECT 64.730 59.690 72.120 59.860 ;
        RECT 75.050 59.690 83.190 60.810 ;
        RECT 64.730 57.970 83.190 59.690 ;
        RECT 88.190 59.340 92.680 61.750 ;
        RECT 100.790 61.420 104.420 61.870 ;
        RECT 106.420 61.820 110.910 61.850 ;
        RECT 119.190 61.820 124.420 62.280 ;
        RECT 129.820 61.820 130.050 62.280 ;
        RECT 137.960 61.970 143.190 62.430 ;
        RECT 148.590 61.970 148.820 62.430 ;
        RECT 106.215 61.590 111.215 61.820 ;
        RECT 64.730 56.520 70.480 57.970 ;
        RECT 64.750 54.945 70.440 56.520 ;
        RECT 77.840 53.390 83.190 57.970 ;
        RECT 87.010 57.130 87.240 57.600 ;
        RECT 86.900 56.530 87.330 57.130 ;
        RECT 88.590 57.090 88.820 57.600 ;
        RECT 90.170 57.090 90.400 57.600 ;
        RECT 88.530 56.590 88.960 57.090 ;
        RECT 90.050 56.590 90.480 57.090 ;
        RECT 91.750 57.080 91.980 57.600 ;
        RECT 93.330 57.080 93.560 57.600 ;
        RECT 87.010 17.600 87.240 56.530 ;
        RECT 88.590 17.600 88.820 56.590 ;
        RECT 90.170 17.600 90.400 56.590 ;
        RECT 91.640 56.580 92.070 57.080 ;
        RECT 93.180 56.580 93.610 57.080 ;
        RECT 91.750 17.600 91.980 56.580 ;
        RECT 93.330 17.600 93.560 56.580 ;
        RECT 100.810 54.170 102.610 61.420 ;
        RECT 106.420 59.180 110.910 61.590 ;
        RECT 119.190 61.370 122.820 61.820 ;
        RECT 124.820 61.770 129.310 61.800 ;
        RECT 124.615 61.540 129.615 61.770 ;
        RECT 105.240 56.970 105.470 57.440 ;
        RECT 105.130 56.370 105.560 56.970 ;
        RECT 106.820 56.930 107.050 57.440 ;
        RECT 108.400 56.930 108.630 57.440 ;
        RECT 106.760 56.430 107.190 56.930 ;
        RECT 108.280 56.430 108.710 56.930 ;
        RECT 109.980 56.920 110.210 57.440 ;
        RECT 111.560 56.920 111.790 57.440 ;
        RECT 105.240 17.440 105.470 56.370 ;
        RECT 106.820 17.440 107.050 56.430 ;
        RECT 108.400 17.440 108.630 56.430 ;
        RECT 109.870 56.420 110.300 56.920 ;
        RECT 111.410 56.420 111.840 56.920 ;
        RECT 109.980 17.440 110.210 56.420 ;
        RECT 111.560 17.440 111.790 56.420 ;
        RECT 119.220 54.100 121.330 61.370 ;
        RECT 124.820 59.130 129.310 61.540 ;
        RECT 137.960 61.520 141.590 61.970 ;
        RECT 143.590 61.920 148.080 61.950 ;
        RECT 143.385 61.690 148.385 61.920 ;
        RECT 123.640 56.920 123.870 57.390 ;
        RECT 123.530 56.320 123.960 56.920 ;
        RECT 125.220 56.880 125.450 57.390 ;
        RECT 126.800 56.880 127.030 57.390 ;
        RECT 125.160 56.380 125.590 56.880 ;
        RECT 126.680 56.380 127.110 56.880 ;
        RECT 128.380 56.870 128.610 57.390 ;
        RECT 129.960 56.870 130.190 57.390 ;
        RECT 123.640 17.390 123.870 56.320 ;
        RECT 125.220 17.390 125.450 56.380 ;
        RECT 126.800 17.390 127.030 56.380 ;
        RECT 128.270 56.370 128.700 56.870 ;
        RECT 129.810 56.370 130.240 56.870 ;
        RECT 128.380 17.390 128.610 56.370 ;
        RECT 129.960 17.390 130.190 56.370 ;
        RECT 138.030 54.190 140.140 61.520 ;
        RECT 143.590 59.280 148.080 61.690 ;
        RECT 142.410 57.070 142.640 57.540 ;
        RECT 142.300 56.470 142.730 57.070 ;
        RECT 143.990 57.030 144.220 57.540 ;
        RECT 145.570 57.030 145.800 57.540 ;
        RECT 143.930 56.530 144.360 57.030 ;
        RECT 145.450 56.530 145.880 57.030 ;
        RECT 147.150 57.020 147.380 57.540 ;
        RECT 148.730 57.020 148.960 57.540 ;
        RECT 142.410 17.540 142.640 56.470 ;
        RECT 143.990 17.540 144.220 56.530 ;
        RECT 145.570 17.540 145.800 56.530 ;
        RECT 147.040 56.520 147.470 57.020 ;
        RECT 148.580 56.520 149.010 57.020 ;
        RECT 147.150 17.540 147.380 56.520 ;
        RECT 148.730 17.540 148.960 56.520 ;
        RECT 178.060 17.220 182.050 31.190 ;
        RECT 178.060 6.990 182.050 10.620 ;
        RECT 56.750 -1.740 60.380 -1.330 ;
        RECT 73.800 -1.740 77.430 -1.330 ;
        RECT 56.750 -2.200 61.980 -1.740 ;
        RECT 67.380 -2.200 67.610 -1.740 ;
        RECT 73.800 -2.200 79.030 -1.740 ;
        RECT 84.430 -2.200 84.660 -1.740 ;
        RECT 99.640 -1.760 103.270 -1.350 ;
        RECT 120.660 -1.760 124.290 -1.350 ;
        RECT 56.750 -2.650 60.380 -2.200 ;
        RECT 62.380 -2.250 66.870 -2.220 ;
        RECT 62.175 -2.480 67.175 -2.250 ;
        RECT 56.920 -11.860 58.960 -2.650 ;
        RECT 62.380 -4.890 66.870 -2.480 ;
        RECT 73.800 -2.650 77.430 -2.200 ;
        RECT 99.640 -2.220 104.870 -1.760 ;
        RECT 110.270 -2.220 110.500 -1.760 ;
        RECT 120.660 -2.220 125.890 -1.760 ;
        RECT 131.290 -2.220 131.520 -1.760 ;
        RECT 144.730 -1.790 148.360 -1.380 ;
        RECT 162.800 -1.790 166.430 -1.380 ;
        RECT 79.430 -2.250 83.920 -2.220 ;
        RECT 79.225 -2.480 84.225 -2.250 ;
        RECT 61.200 -7.100 61.430 -6.630 ;
        RECT 61.090 -7.700 61.520 -7.100 ;
        RECT 62.780 -7.140 63.010 -6.630 ;
        RECT 64.360 -7.140 64.590 -6.630 ;
        RECT 62.720 -7.640 63.150 -7.140 ;
        RECT 64.240 -7.640 64.670 -7.140 ;
        RECT 65.940 -7.150 66.170 -6.630 ;
        RECT 67.520 -7.150 67.750 -6.630 ;
        RECT 61.200 -46.630 61.430 -7.700 ;
        RECT 62.780 -46.630 63.010 -7.640 ;
        RECT 64.360 -46.630 64.590 -7.640 ;
        RECT 65.830 -7.650 66.260 -7.150 ;
        RECT 67.370 -7.650 67.800 -7.150 ;
        RECT 65.940 -46.630 66.170 -7.650 ;
        RECT 67.520 -46.630 67.750 -7.650 ;
        RECT 73.890 -11.940 75.930 -2.650 ;
        RECT 79.430 -4.890 83.920 -2.480 ;
        RECT 99.640 -2.670 103.270 -2.220 ;
        RECT 105.270 -2.270 109.760 -2.240 ;
        RECT 105.065 -2.500 110.065 -2.270 ;
        RECT 78.250 -7.100 78.480 -6.630 ;
        RECT 78.140 -7.700 78.570 -7.100 ;
        RECT 79.830 -7.140 80.060 -6.630 ;
        RECT 81.410 -7.140 81.640 -6.630 ;
        RECT 79.770 -7.640 80.200 -7.140 ;
        RECT 81.290 -7.640 81.720 -7.140 ;
        RECT 82.990 -7.150 83.220 -6.630 ;
        RECT 84.570 -7.150 84.800 -6.630 ;
        RECT 78.250 -46.630 78.480 -7.700 ;
        RECT 79.830 -46.630 80.060 -7.640 ;
        RECT 81.410 -46.630 81.640 -7.640 ;
        RECT 82.880 -7.650 83.310 -7.150 ;
        RECT 84.420 -7.650 84.850 -7.150 ;
        RECT 82.990 -46.630 83.220 -7.650 ;
        RECT 84.570 -46.630 84.800 -7.650 ;
        RECT 99.660 -11.900 101.700 -2.670 ;
        RECT 105.270 -4.910 109.760 -2.500 ;
        RECT 120.660 -2.670 124.290 -2.220 ;
        RECT 126.290 -2.270 130.780 -2.240 ;
        RECT 144.730 -2.250 149.960 -1.790 ;
        RECT 155.360 -2.250 155.590 -1.790 ;
        RECT 162.800 -2.250 168.030 -1.790 ;
        RECT 173.430 -2.250 173.660 -1.790 ;
        RECT 126.085 -2.500 131.085 -2.270 ;
        RECT 104.090 -7.120 104.320 -6.650 ;
        RECT 103.980 -7.720 104.410 -7.120 ;
        RECT 105.670 -7.160 105.900 -6.650 ;
        RECT 107.250 -7.160 107.480 -6.650 ;
        RECT 105.610 -7.660 106.040 -7.160 ;
        RECT 107.130 -7.660 107.560 -7.160 ;
        RECT 108.830 -7.170 109.060 -6.650 ;
        RECT 110.410 -7.170 110.640 -6.650 ;
        RECT 104.090 -46.650 104.320 -7.720 ;
        RECT 105.670 -46.650 105.900 -7.660 ;
        RECT 107.250 -46.650 107.480 -7.660 ;
        RECT 108.720 -7.670 109.150 -7.170 ;
        RECT 110.260 -7.670 110.690 -7.170 ;
        RECT 108.830 -46.650 109.060 -7.670 ;
        RECT 110.410 -46.650 110.640 -7.670 ;
        RECT 120.800 -11.810 122.840 -2.670 ;
        RECT 126.290 -4.910 130.780 -2.500 ;
        RECT 144.730 -2.700 148.360 -2.250 ;
        RECT 150.360 -2.300 154.850 -2.270 ;
        RECT 150.155 -2.530 155.155 -2.300 ;
        RECT 125.110 -7.120 125.340 -6.650 ;
        RECT 125.000 -7.720 125.430 -7.120 ;
        RECT 126.690 -7.160 126.920 -6.650 ;
        RECT 128.270 -7.160 128.500 -6.650 ;
        RECT 126.630 -7.660 127.060 -7.160 ;
        RECT 128.150 -7.660 128.580 -7.160 ;
        RECT 129.850 -7.170 130.080 -6.650 ;
        RECT 131.430 -7.170 131.660 -6.650 ;
        RECT 125.110 -46.650 125.340 -7.720 ;
        RECT 126.690 -46.650 126.920 -7.660 ;
        RECT 128.270 -46.650 128.500 -7.660 ;
        RECT 129.740 -7.670 130.170 -7.170 ;
        RECT 131.280 -7.670 131.710 -7.170 ;
        RECT 129.850 -46.650 130.080 -7.670 ;
        RECT 131.430 -46.650 131.660 -7.670 ;
        RECT 144.760 -11.880 146.800 -2.700 ;
        RECT 150.360 -4.940 154.850 -2.530 ;
        RECT 162.800 -2.700 166.430 -2.250 ;
        RECT 168.430 -2.300 172.920 -2.270 ;
        RECT 168.225 -2.530 173.225 -2.300 ;
        RECT 149.180 -7.150 149.410 -6.680 ;
        RECT 149.070 -7.750 149.500 -7.150 ;
        RECT 150.760 -7.190 150.990 -6.680 ;
        RECT 152.340 -7.190 152.570 -6.680 ;
        RECT 150.700 -7.690 151.130 -7.190 ;
        RECT 152.220 -7.690 152.650 -7.190 ;
        RECT 153.920 -7.200 154.150 -6.680 ;
        RECT 155.500 -7.200 155.730 -6.680 ;
        RECT 149.180 -46.680 149.410 -7.750 ;
        RECT 150.760 -46.680 150.990 -7.690 ;
        RECT 152.340 -46.680 152.570 -7.690 ;
        RECT 153.810 -7.700 154.240 -7.200 ;
        RECT 155.350 -7.700 155.780 -7.200 ;
        RECT 153.920 -46.680 154.150 -7.700 ;
        RECT 155.500 -46.680 155.730 -7.700 ;
        RECT 162.890 -11.860 164.930 -2.700 ;
        RECT 168.430 -4.940 172.920 -2.530 ;
        RECT 167.250 -7.150 167.480 -6.680 ;
        RECT 167.140 -7.750 167.570 -7.150 ;
        RECT 168.830 -7.190 169.060 -6.680 ;
        RECT 170.410 -7.190 170.640 -6.680 ;
        RECT 168.770 -7.690 169.200 -7.190 ;
        RECT 170.290 -7.690 170.720 -7.190 ;
        RECT 171.990 -7.200 172.220 -6.680 ;
        RECT 173.570 -7.200 173.800 -6.680 ;
        RECT 167.250 -46.680 167.480 -7.750 ;
        RECT 168.830 -46.680 169.060 -7.690 ;
        RECT 170.410 -46.680 170.640 -7.690 ;
        RECT 171.880 -7.700 172.310 -7.200 ;
        RECT 173.420 -7.700 173.850 -7.200 ;
        RECT 171.990 -46.680 172.220 -7.700 ;
        RECT 173.570 -46.680 173.800 -7.700 ;
        RECT 178.050 -46.400 182.020 -43.350 ;
        RECT 178.070 -57.480 182.030 -53.560 ;
        RECT 135.020 -69.040 137.480 -68.840 ;
        RECT 85.840 -69.450 89.470 -69.040 ;
        RECT 102.230 -69.450 105.860 -69.040 ;
        RECT 118.190 -69.450 121.820 -69.040 ;
        RECT 135.020 -69.450 138.810 -69.040 ;
        RECT 85.840 -69.910 91.070 -69.450 ;
        RECT 96.470 -69.910 96.700 -69.450 ;
        RECT 102.230 -69.910 107.460 -69.450 ;
        RECT 112.860 -69.910 113.090 -69.450 ;
        RECT 118.190 -69.910 123.420 -69.450 ;
        RECT 128.820 -69.910 129.050 -69.450 ;
        RECT 135.020 -69.910 140.410 -69.450 ;
        RECT 145.810 -69.910 146.040 -69.450 ;
        RECT 85.840 -70.360 89.470 -69.910 ;
        RECT 91.470 -69.960 95.960 -69.930 ;
        RECT 91.265 -70.190 96.265 -69.960 ;
        RECT 85.840 -79.140 88.010 -70.360 ;
        RECT 91.470 -72.600 95.960 -70.190 ;
        RECT 102.230 -70.360 105.860 -69.910 ;
        RECT 107.860 -69.960 112.350 -69.930 ;
        RECT 107.655 -70.190 112.655 -69.960 ;
        RECT 90.290 -74.810 90.520 -74.340 ;
        RECT 90.180 -75.410 90.610 -74.810 ;
        RECT 91.870 -74.850 92.100 -74.340 ;
        RECT 93.450 -74.850 93.680 -74.340 ;
        RECT 91.810 -75.350 92.240 -74.850 ;
        RECT 93.330 -75.350 93.760 -74.850 ;
        RECT 95.030 -74.860 95.260 -74.340 ;
        RECT 96.610 -74.860 96.840 -74.340 ;
        RECT 90.290 -114.340 90.520 -75.410 ;
        RECT 91.870 -114.340 92.100 -75.350 ;
        RECT 93.450 -114.340 93.680 -75.350 ;
        RECT 94.920 -75.360 95.350 -74.860 ;
        RECT 96.460 -75.360 96.890 -74.860 ;
        RECT 95.030 -114.340 95.260 -75.360 ;
        RECT 96.610 -114.340 96.840 -75.360 ;
        RECT 102.370 -79.120 104.540 -70.360 ;
        RECT 107.860 -72.600 112.350 -70.190 ;
        RECT 118.190 -70.360 121.820 -69.910 ;
        RECT 123.820 -69.960 128.310 -69.930 ;
        RECT 123.615 -70.190 128.615 -69.960 ;
        RECT 106.680 -74.810 106.910 -74.340 ;
        RECT 106.570 -75.410 107.000 -74.810 ;
        RECT 108.260 -74.850 108.490 -74.340 ;
        RECT 109.840 -74.850 110.070 -74.340 ;
        RECT 108.200 -75.350 108.630 -74.850 ;
        RECT 109.720 -75.350 110.150 -74.850 ;
        RECT 111.420 -74.860 111.650 -74.340 ;
        RECT 113.000 -74.860 113.230 -74.340 ;
        RECT 106.680 -114.340 106.910 -75.410 ;
        RECT 108.260 -114.340 108.490 -75.350 ;
        RECT 109.840 -114.340 110.070 -75.350 ;
        RECT 111.310 -75.360 111.740 -74.860 ;
        RECT 112.850 -75.360 113.280 -74.860 ;
        RECT 111.420 -114.340 111.650 -75.360 ;
        RECT 113.000 -114.340 113.230 -75.360 ;
        RECT 118.440 -79.050 120.610 -70.360 ;
        RECT 123.820 -72.600 128.310 -70.190 ;
        RECT 135.020 -70.360 138.810 -69.910 ;
        RECT 140.810 -69.960 145.300 -69.930 ;
        RECT 140.605 -70.190 145.605 -69.960 ;
        RECT 122.640 -74.810 122.870 -74.340 ;
        RECT 122.530 -75.410 122.960 -74.810 ;
        RECT 124.220 -74.850 124.450 -74.340 ;
        RECT 125.800 -74.850 126.030 -74.340 ;
        RECT 124.160 -75.350 124.590 -74.850 ;
        RECT 125.680 -75.350 126.110 -74.850 ;
        RECT 127.380 -74.860 127.610 -74.340 ;
        RECT 128.960 -74.860 129.190 -74.340 ;
        RECT 122.640 -114.340 122.870 -75.410 ;
        RECT 124.220 -114.340 124.450 -75.350 ;
        RECT 125.800 -114.340 126.030 -75.350 ;
        RECT 127.270 -75.360 127.700 -74.860 ;
        RECT 128.810 -75.360 129.240 -74.860 ;
        RECT 127.380 -114.340 127.610 -75.360 ;
        RECT 128.960 -114.340 129.190 -75.360 ;
        RECT 135.020 -79.080 137.480 -70.360 ;
        RECT 140.810 -72.600 145.300 -70.190 ;
        RECT 139.630 -74.810 139.860 -74.340 ;
        RECT 139.520 -75.410 139.950 -74.810 ;
        RECT 141.210 -74.850 141.440 -74.340 ;
        RECT 142.790 -74.850 143.020 -74.340 ;
        RECT 141.150 -75.350 141.580 -74.850 ;
        RECT 142.670 -75.350 143.100 -74.850 ;
        RECT 144.370 -74.860 144.600 -74.340 ;
        RECT 145.950 -74.860 146.180 -74.340 ;
        RECT 139.630 -114.340 139.860 -75.410 ;
        RECT 141.210 -114.340 141.440 -75.350 ;
        RECT 142.790 -114.340 143.020 -75.350 ;
        RECT 144.260 -75.360 144.690 -74.860 ;
        RECT 145.800 -75.360 146.230 -74.860 ;
        RECT 144.370 -114.340 144.600 -75.360 ;
        RECT 145.950 -114.340 146.180 -75.360 ;
      LAYER via ;
        RECT 100.910 61.690 101.460 62.220 ;
        RECT 101.760 61.690 102.310 62.220 ;
        RECT 119.320 61.640 119.870 62.170 ;
        RECT 120.180 61.650 120.730 62.180 ;
        RECT 88.420 59.460 92.520 60.030 ;
        RECT 78.180 57.020 79.310 58.460 ;
        RECT 79.770 56.990 80.900 58.430 ;
        RECT 81.640 56.960 82.770 58.400 ;
        RECT 86.970 56.640 87.270 56.960 ;
        RECT 88.600 56.670 88.890 57.000 ;
        RECT 90.120 56.670 90.410 57.000 ;
        RECT 91.710 56.660 92.000 56.990 ;
        RECT 78.060 53.640 79.190 55.080 ;
        RECT 79.630 53.610 80.760 55.050 ;
        RECT 81.540 53.640 82.670 55.080 ;
        RECT 93.250 56.660 93.540 56.990 ;
        RECT 106.650 59.300 110.750 59.870 ;
        RECT 105.200 56.480 105.500 56.800 ;
        RECT 106.830 56.510 107.120 56.840 ;
        RECT 108.350 56.510 108.640 56.840 ;
        RECT 109.940 56.500 110.230 56.830 ;
        RECT 101.060 54.440 101.380 54.800 ;
        RECT 101.860 54.500 102.180 54.860 ;
        RECT 111.480 56.500 111.770 56.830 ;
        RECT 125.050 59.250 129.150 59.820 ;
        RECT 123.600 56.430 123.900 56.750 ;
        RECT 125.230 56.460 125.520 56.790 ;
        RECT 126.750 56.460 127.040 56.790 ;
        RECT 128.340 56.450 128.630 56.780 ;
        RECT 119.410 54.260 119.880 54.820 ;
        RECT 120.680 54.290 121.150 54.850 ;
        RECT 129.880 56.450 130.170 56.780 ;
        RECT 143.820 59.400 147.920 59.970 ;
        RECT 142.370 56.580 142.670 56.900 ;
        RECT 144.000 56.610 144.290 56.940 ;
        RECT 145.520 56.610 145.810 56.940 ;
        RECT 147.110 56.600 147.400 56.930 ;
        RECT 138.330 54.340 138.800 54.900 ;
        RECT 139.480 54.420 139.950 54.980 ;
        RECT 148.650 56.600 148.940 56.930 ;
        RECT 178.260 30.360 179.880 31.030 ;
        RECT 180.310 30.330 181.930 31.000 ;
        RECT 178.250 29.440 179.870 30.110 ;
        RECT 180.290 29.390 181.910 30.060 ;
        RECT 178.230 28.400 179.850 29.070 ;
        RECT 180.270 28.440 181.890 29.110 ;
        RECT 178.230 27.530 179.850 28.200 ;
        RECT 180.260 27.530 181.880 28.200 ;
        RECT 178.200 8.940 179.820 9.610 ;
        RECT 180.340 8.940 181.960 9.610 ;
        RECT 178.210 8.010 179.830 8.680 ;
        RECT 180.350 8.020 181.970 8.690 ;
        RECT 178.190 7.110 179.810 7.780 ;
        RECT 180.320 7.140 181.940 7.810 ;
        RECT 57.190 -2.410 57.720 -1.720 ;
        RECT 58.210 -2.350 58.740 -1.660 ;
        RECT 74.160 -2.390 74.690 -1.700 ;
        RECT 75.120 -2.310 75.650 -1.620 ;
        RECT 62.610 -4.770 66.710 -4.200 ;
        RECT 61.160 -7.590 61.460 -7.270 ;
        RECT 62.790 -7.560 63.080 -7.230 ;
        RECT 64.310 -7.560 64.600 -7.230 ;
        RECT 65.900 -7.570 66.190 -7.240 ;
        RECT 57.170 -11.540 57.700 -10.850 ;
        RECT 58.010 -11.480 58.540 -10.790 ;
        RECT 67.440 -7.570 67.730 -7.240 ;
        RECT 99.880 -2.500 100.500 -1.570 ;
        RECT 100.920 -2.480 101.540 -1.550 ;
        RECT 121.020 -2.440 121.640 -1.510 ;
        RECT 122.030 -2.410 122.650 -1.480 ;
        RECT 79.660 -4.770 83.760 -4.200 ;
        RECT 78.210 -7.590 78.510 -7.270 ;
        RECT 79.840 -7.560 80.130 -7.230 ;
        RECT 81.360 -7.560 81.650 -7.230 ;
        RECT 82.950 -7.570 83.240 -7.240 ;
        RECT 74.180 -11.520 74.710 -10.830 ;
        RECT 75.130 -11.520 75.660 -10.830 ;
        RECT 84.490 -7.570 84.780 -7.240 ;
        RECT 144.950 -2.450 145.570 -1.520 ;
        RECT 146.000 -2.440 146.620 -1.510 ;
        RECT 105.500 -4.790 109.600 -4.220 ;
        RECT 104.050 -7.610 104.350 -7.290 ;
        RECT 105.680 -7.580 105.970 -7.250 ;
        RECT 107.200 -7.580 107.490 -7.250 ;
        RECT 108.790 -7.590 109.080 -7.260 ;
        RECT 99.820 -11.560 100.440 -10.630 ;
        RECT 100.760 -11.540 101.380 -10.610 ;
        RECT 110.330 -7.590 110.620 -7.260 ;
        RECT 126.520 -4.790 130.620 -4.220 ;
        RECT 125.070 -7.610 125.370 -7.290 ;
        RECT 126.700 -7.580 126.990 -7.250 ;
        RECT 128.220 -7.580 128.510 -7.250 ;
        RECT 129.810 -7.590 130.100 -7.260 ;
        RECT 121.050 -11.500 121.670 -10.570 ;
        RECT 122.030 -11.470 122.650 -10.540 ;
        RECT 131.350 -7.590 131.640 -7.260 ;
        RECT 163.100 -2.560 163.720 -1.630 ;
        RECT 164.080 -2.540 164.740 -1.580 ;
        RECT 150.590 -4.820 154.690 -4.250 ;
        RECT 149.140 -7.640 149.440 -7.320 ;
        RECT 150.770 -7.610 151.060 -7.280 ;
        RECT 152.290 -7.610 152.580 -7.280 ;
        RECT 153.880 -7.620 154.170 -7.290 ;
        RECT 145.000 -11.500 145.620 -10.570 ;
        RECT 145.960 -11.510 146.580 -10.580 ;
        RECT 155.420 -7.620 155.710 -7.290 ;
        RECT 168.660 -4.820 172.760 -4.250 ;
        RECT 167.210 -7.640 167.510 -7.320 ;
        RECT 168.840 -7.610 169.130 -7.280 ;
        RECT 170.360 -7.610 170.650 -7.280 ;
        RECT 171.950 -7.620 172.240 -7.290 ;
        RECT 163.100 -11.530 163.720 -10.600 ;
        RECT 164.140 -11.440 164.760 -10.510 ;
        RECT 173.490 -7.620 173.780 -7.290 ;
        RECT 178.560 -44.520 179.450 -43.780 ;
        RECT 180.460 -44.540 181.350 -43.800 ;
        RECT 178.520 -46.010 179.410 -45.270 ;
        RECT 180.450 -46.000 181.340 -45.260 ;
        RECT 178.470 -54.760 179.360 -54.020 ;
        RECT 180.670 -54.720 181.560 -53.980 ;
        RECT 178.420 -57.190 179.310 -56.450 ;
        RECT 180.670 -57.170 181.560 -56.430 ;
        RECT 85.980 -70.240 86.520 -69.390 ;
        RECT 87.170 -70.160 87.710 -69.310 ;
        RECT 102.500 -70.180 103.040 -69.330 ;
        RECT 103.720 -70.180 104.260 -69.330 ;
        RECT 118.550 -70.160 119.090 -69.310 ;
        RECT 91.700 -72.480 95.800 -71.910 ;
        RECT 90.250 -75.300 90.550 -74.980 ;
        RECT 91.880 -75.270 92.170 -74.940 ;
        RECT 93.400 -75.270 93.690 -74.940 ;
        RECT 94.990 -75.280 95.280 -74.950 ;
        RECT 85.960 -78.780 86.570 -77.760 ;
        RECT 87.120 -78.740 87.730 -77.720 ;
        RECT 96.530 -75.280 96.820 -74.950 ;
        RECT 119.820 -70.200 120.360 -69.350 ;
        RECT 108.090 -72.480 112.190 -71.910 ;
        RECT 106.640 -75.300 106.940 -74.980 ;
        RECT 108.270 -75.270 108.560 -74.940 ;
        RECT 109.790 -75.270 110.080 -74.940 ;
        RECT 111.380 -75.280 111.670 -74.950 ;
        RECT 102.700 -78.280 103.240 -77.430 ;
        RECT 103.750 -78.300 104.290 -77.450 ;
        RECT 112.920 -75.280 113.210 -74.950 ;
        RECT 124.050 -72.480 128.150 -71.910 ;
        RECT 135.180 -70.410 137.350 -69.050 ;
        RECT 122.600 -75.300 122.900 -74.980 ;
        RECT 124.230 -75.270 124.520 -74.940 ;
        RECT 125.750 -75.270 126.040 -74.940 ;
        RECT 127.340 -75.280 127.630 -74.950 ;
        RECT 118.580 -78.520 119.120 -77.670 ;
        RECT 119.710 -78.540 120.250 -77.690 ;
        RECT 128.880 -75.280 129.170 -74.950 ;
        RECT 141.040 -72.480 145.140 -71.910 ;
        RECT 139.590 -75.300 139.890 -74.980 ;
        RECT 141.220 -75.270 141.510 -74.940 ;
        RECT 142.740 -75.270 143.030 -74.940 ;
        RECT 144.330 -75.280 144.620 -74.950 ;
        RECT 145.870 -75.280 146.160 -74.950 ;
      LAYER met2 ;
        RECT 86.900 59.310 93.600 60.090 ;
        RECT 77.840 55.400 83.190 58.990 ;
        RECT 86.900 56.530 87.330 59.310 ;
        RECT 88.530 57.090 88.950 59.310 ;
        RECT 90.050 57.090 90.470 59.310 ;
        RECT 88.530 56.590 88.960 57.090 ;
        RECT 90.050 56.590 90.480 57.090 ;
        RECT 91.640 57.080 92.060 59.310 ;
        RECT 93.180 57.080 93.600 59.310 ;
        RECT 91.640 56.580 92.070 57.080 ;
        RECT 93.180 56.580 93.610 57.080 ;
        RECT 100.810 55.400 102.610 62.720 ;
        RECT 105.130 59.150 111.830 59.930 ;
        RECT 105.130 56.370 105.560 59.150 ;
        RECT 106.760 56.930 107.180 59.150 ;
        RECT 108.280 56.930 108.700 59.150 ;
        RECT 106.760 56.430 107.190 56.930 ;
        RECT 108.280 56.430 108.710 56.930 ;
        RECT 109.870 56.920 110.290 59.150 ;
        RECT 111.410 56.920 111.830 59.150 ;
        RECT 109.870 56.420 110.300 56.920 ;
        RECT 111.410 56.420 111.840 56.920 ;
        RECT 119.220 55.400 121.330 62.610 ;
        RECT 123.530 59.100 130.230 59.880 ;
        RECT 123.530 56.320 123.960 59.100 ;
        RECT 125.160 56.880 125.580 59.100 ;
        RECT 126.680 56.880 127.100 59.100 ;
        RECT 125.160 56.380 125.590 56.880 ;
        RECT 126.680 56.380 127.110 56.880 ;
        RECT 128.270 56.870 128.690 59.100 ;
        RECT 129.810 56.870 130.230 59.100 ;
        RECT 128.270 56.370 128.700 56.870 ;
        RECT 129.810 56.370 130.240 56.870 ;
        RECT 138.030 55.400 140.140 62.700 ;
        RECT 142.300 59.250 149.000 60.030 ;
        RECT 142.300 56.470 142.730 59.250 ;
        RECT 143.930 57.030 144.350 59.250 ;
        RECT 145.450 57.030 145.870 59.250 ;
        RECT 143.930 56.530 144.360 57.030 ;
        RECT 145.450 56.530 145.880 57.030 ;
        RECT 147.040 57.020 147.460 59.250 ;
        RECT 148.580 57.020 149.000 59.250 ;
        RECT 147.040 56.520 147.470 57.020 ;
        RECT 148.580 56.520 149.010 57.020 ;
        RECT 77.840 55.360 180.360 55.400 ;
        RECT 77.840 53.390 182.000 55.360 ;
        RECT 178.070 26.490 182.000 53.390 ;
        RECT 56.920 -10.040 58.960 -1.430 ;
        RECT 61.090 -4.920 67.790 -4.140 ;
        RECT 61.090 -7.700 61.520 -4.920 ;
        RECT 62.720 -7.140 63.140 -4.920 ;
        RECT 64.240 -7.140 64.660 -4.920 ;
        RECT 62.720 -7.640 63.150 -7.140 ;
        RECT 64.240 -7.640 64.670 -7.140 ;
        RECT 65.830 -7.150 66.250 -4.920 ;
        RECT 67.370 -7.150 67.790 -4.920 ;
        RECT 65.830 -7.650 66.260 -7.150 ;
        RECT 67.370 -7.650 67.800 -7.150 ;
        RECT 73.890 -10.040 75.930 -1.510 ;
        RECT 78.140 -4.920 84.840 -4.140 ;
        RECT 78.140 -7.700 78.570 -4.920 ;
        RECT 79.770 -7.140 80.190 -4.920 ;
        RECT 81.290 -7.140 81.710 -4.920 ;
        RECT 79.770 -7.640 80.200 -7.140 ;
        RECT 81.290 -7.640 81.720 -7.140 ;
        RECT 82.880 -7.150 83.300 -4.920 ;
        RECT 84.420 -7.150 84.840 -4.920 ;
        RECT 82.880 -7.650 83.310 -7.150 ;
        RECT 84.420 -7.650 84.850 -7.150 ;
        RECT 99.660 -10.040 101.700 -1.470 ;
        RECT 103.980 -4.940 110.680 -4.160 ;
        RECT 103.980 -7.720 104.410 -4.940 ;
        RECT 105.610 -7.160 106.030 -4.940 ;
        RECT 107.130 -7.160 107.550 -4.940 ;
        RECT 105.610 -7.660 106.040 -7.160 ;
        RECT 107.130 -7.660 107.560 -7.160 ;
        RECT 108.720 -7.170 109.140 -4.940 ;
        RECT 110.260 -7.170 110.680 -4.940 ;
        RECT 108.720 -7.670 109.150 -7.170 ;
        RECT 110.260 -7.670 110.690 -7.170 ;
        RECT 120.800 -10.040 122.840 -1.380 ;
        RECT 125.000 -4.940 131.700 -4.160 ;
        RECT 125.000 -7.720 125.430 -4.940 ;
        RECT 126.630 -7.160 127.050 -4.940 ;
        RECT 128.150 -7.160 128.570 -4.940 ;
        RECT 126.630 -7.660 127.060 -7.160 ;
        RECT 128.150 -7.660 128.580 -7.160 ;
        RECT 129.740 -7.170 130.160 -4.940 ;
        RECT 131.280 -7.170 131.700 -4.940 ;
        RECT 129.740 -7.670 130.170 -7.170 ;
        RECT 131.280 -7.670 131.710 -7.170 ;
        RECT 144.760 -10.040 146.800 -1.450 ;
        RECT 149.070 -4.970 155.770 -4.190 ;
        RECT 149.070 -7.750 149.500 -4.970 ;
        RECT 150.700 -7.190 151.120 -4.970 ;
        RECT 152.220 -7.190 152.640 -4.970 ;
        RECT 150.700 -7.690 151.130 -7.190 ;
        RECT 152.220 -7.690 152.650 -7.190 ;
        RECT 153.810 -7.200 154.230 -4.970 ;
        RECT 155.350 -7.200 155.770 -4.970 ;
        RECT 153.810 -7.700 154.240 -7.200 ;
        RECT 155.350 -7.700 155.780 -7.200 ;
        RECT 162.890 -10.040 164.930 -1.430 ;
        RECT 167.140 -4.970 173.840 -4.190 ;
        RECT 167.140 -7.750 167.570 -4.970 ;
        RECT 168.770 -7.190 169.190 -4.970 ;
        RECT 170.290 -7.190 170.710 -4.970 ;
        RECT 168.770 -7.690 169.200 -7.190 ;
        RECT 170.290 -7.690 170.720 -7.190 ;
        RECT 171.880 -7.200 172.300 -4.970 ;
        RECT 173.420 -7.200 173.840 -4.970 ;
        RECT 171.880 -7.700 172.310 -7.200 ;
        RECT 173.420 -7.700 173.850 -7.200 ;
        RECT 178.070 -10.040 182.000 10.520 ;
        RECT 56.710 -13.660 182.000 -10.040 ;
        RECT 178.070 -46.410 182.000 -13.660 ;
        RECT 178.070 -61.780 182.000 -53.560 ;
        RECT 85.840 -76.430 88.010 -69.230 ;
        RECT 90.180 -72.630 96.880 -71.850 ;
        RECT 90.180 -75.410 90.610 -72.630 ;
        RECT 91.810 -74.850 92.230 -72.630 ;
        RECT 93.330 -74.850 93.750 -72.630 ;
        RECT 91.810 -75.350 92.240 -74.850 ;
        RECT 93.330 -75.350 93.760 -74.850 ;
        RECT 94.920 -74.860 95.340 -72.630 ;
        RECT 96.460 -74.860 96.880 -72.630 ;
        RECT 94.920 -75.360 95.350 -74.860 ;
        RECT 96.460 -75.360 96.890 -74.860 ;
        RECT 102.370 -76.430 104.540 -69.210 ;
        RECT 106.570 -72.630 113.270 -71.850 ;
        RECT 106.570 -75.410 107.000 -72.630 ;
        RECT 108.200 -74.850 108.620 -72.630 ;
        RECT 109.720 -74.850 110.140 -72.630 ;
        RECT 108.200 -75.350 108.630 -74.850 ;
        RECT 109.720 -75.350 110.150 -74.850 ;
        RECT 111.310 -74.860 111.730 -72.630 ;
        RECT 112.850 -74.860 113.270 -72.630 ;
        RECT 111.310 -75.360 111.740 -74.860 ;
        RECT 112.850 -75.360 113.280 -74.860 ;
        RECT 118.440 -76.430 120.610 -69.140 ;
        RECT 135.020 -70.520 137.490 -68.850 ;
        RECT 178.050 -69.510 182.010 -61.780 ;
        RECT 122.530 -72.630 129.230 -71.850 ;
        RECT 122.530 -75.410 122.960 -72.630 ;
        RECT 124.160 -74.850 124.580 -72.630 ;
        RECT 125.680 -74.850 126.100 -72.630 ;
        RECT 124.160 -75.350 124.590 -74.850 ;
        RECT 125.680 -75.350 126.110 -74.850 ;
        RECT 127.270 -74.860 127.690 -72.630 ;
        RECT 128.810 -74.860 129.230 -72.630 ;
        RECT 127.270 -75.360 127.700 -74.860 ;
        RECT 128.810 -75.360 129.240 -74.860 ;
        RECT 135.180 -76.430 137.350 -70.520 ;
        RECT 139.520 -72.630 146.220 -71.850 ;
        RECT 139.520 -75.410 139.950 -72.630 ;
        RECT 141.150 -74.850 141.570 -72.630 ;
        RECT 142.670 -74.850 143.090 -72.630 ;
        RECT 141.150 -75.350 141.580 -74.850 ;
        RECT 142.670 -75.350 143.100 -74.850 ;
        RECT 144.260 -74.860 144.680 -72.630 ;
        RECT 145.800 -74.860 146.220 -72.630 ;
        RECT 144.260 -75.360 144.690 -74.860 ;
        RECT 145.800 -75.360 146.230 -74.860 ;
        RECT 178.070 -76.430 182.000 -69.510 ;
        RECT 85.480 -80.550 182.000 -76.430 ;
        RECT 178.070 -80.610 182.000 -80.550 ;
  END
END CurrentSteering_3bit_rev3
END LIBRARY

